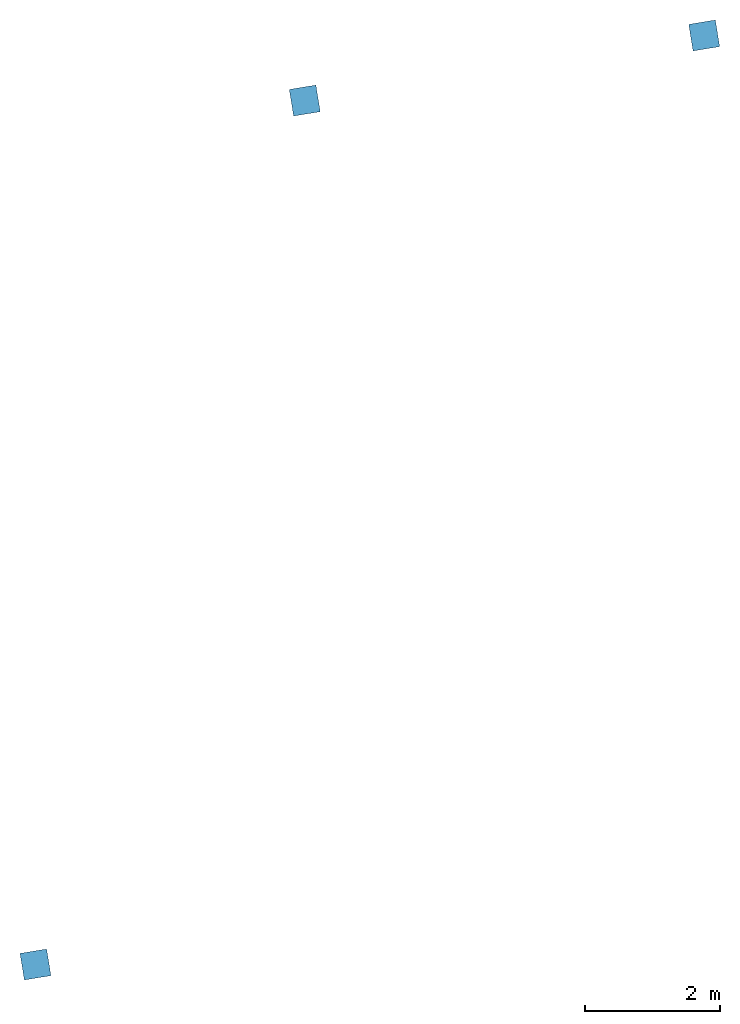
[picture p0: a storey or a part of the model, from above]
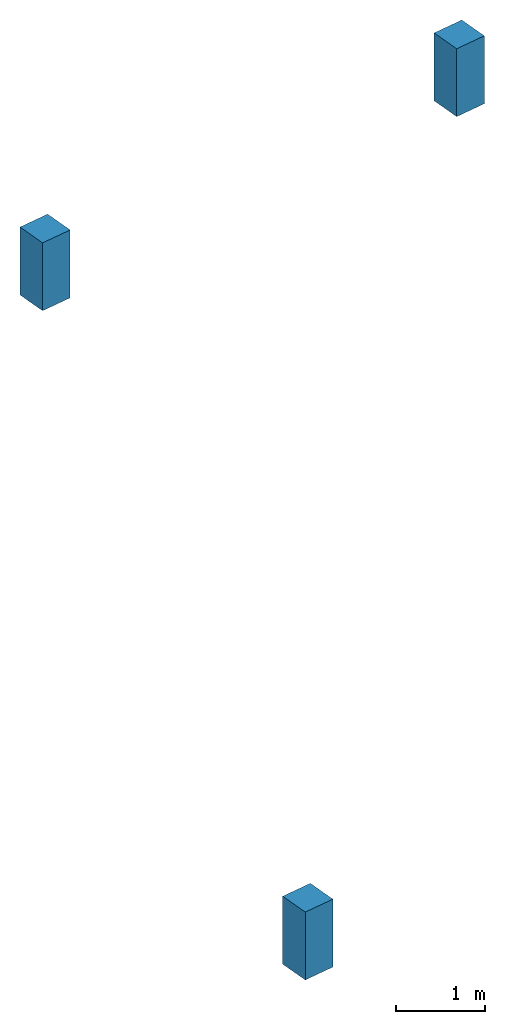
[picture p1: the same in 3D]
Properties of the parts of a building model (IFC2X3), part 1 of 2

# File
Description: ViewDefinition [CoordinationView_V2.0]
File name: BR001-350-201.1.IFC (Edited by Naviate Simple BIM 2022 version 6)
Time: 2026-03-27T10:15:47+01:00
Written by: ODA SDAI 24.12
Made in: Autodesk Revit 25.4.41.14 (ENU) - IFC 25.4.0.27

# IfcProject, 01. Avinor Drift
LongName: Terminal 2 . Satellitt; Phase: Som Bygget

# IfcSite (5)
RefElevation: 0 mm
Name | RefLatitude | RefLongitude
4 x Default | 60, 17, 20, 899658 | 5, 13, 37, 654037
Default | 42, 24, 53, 508911 | -71, -15, -29, -58837

# IfcBuilding (5)
Name | LongName
br001-a-200-1-0001 | br001-a-200-1-0001

3 x Bygning (endres i Project Information) | Bygning (endres i Project Information)

# IfcBuildingStorey: Level:Level - BR001_ARK (4)
In: br001-a-200-1-0001
Name | LongName | Elevation (mm)
H01-Nivå D+0,36 | H01-Nivå D+0,36 | 51360
H02-Nivå F-3,5 m | H02-Nivå F-3,5 m | 55500
H03-Nivå G-5m | H03-Nivå G-5m | 59000
H03-Nivå G-4,3m | H03-Nivå G-4,3m | 59700

# IfcBuildingStorey: Level:Level Elektro, H01-Nivå D+0,36
In: Bygning (endres i Project Information)
LongName: H01-Nivå D+0,36; Elevation: 51360 mm

# IfcBuildingStorey: Level:NO_Nivå_Meter-VVS (3)
In: Bygning (endres i Project Information)
Name | LongName | Elevation (mm)
2 x H01-Nivå D+0,36 | H01-Nivå D+0,36 | 51360
H02-Nivå F-3,5 m | H02-Nivå F-3,5 m | 55500

# IfcBuildingStorey: Level:NSW Kote - Triangel med navn og kote, Arial 2 mm KP (4)
Name | LongName | Elevation (mm)
U01-Nivå B+3,1m | U01-Nivå B+3,1m | 47800
H01-Nivå D+0,36 | H01-Nivå D+0,36 | 51360
H02-Nivå F-3,5 m | H02-Nivå F-3,5 m | 55500
H03-Nivå G-5m | H03-Nivå G-5m | 59000

# IfcBeam: 650*400 (14)
Description: 650*400
ePset_Simplebim - Assembly Level: Leaf
Pset_BeamCommon - Reference: 650*400
Name | In | Material | Width (Simplebim) (mm) | Volume, net (Simplebim) (m3) | Weight, as steel (Simplebim) (kg) | Area, sides, net (Simplebim) (m2) | Length (Simplebim) (mm) | Height (Simplebim) (mm) | Splitting
2 x PLASSTØPTBJELKE | H02-Nivå F-3,5 m | CONCRETE/C55/67 171016 | 400.026 | 1.56 | 12246 | 13.12 | 6000 | 650 | ORIGINAL
2 x PLASSTØPTBJELKE | H01-Nivå D+0,36 | CONCRETE/C55/67 171016 | 400.024 | 1.456 | 11429.6 | 12.28 | 5600 | 650 | ORIGINAL
2 x PLASSTØPTBJELKE | H01-Nivå D+0,36 | CONCRETE/C55/67 171016 | 5999.98 | 2.10217 | 16502.1 | 17.4991 | 6000.02 | 650 | ORIGINAL
2 x PLASSTØPTBJELKE | H02-Nivå F-3,5 m | CONCRETE/C55/67 171016 | 6282.82 | 2.20617 | 17318.5 | 18.3391 | 6282.86 | 650 | ORIGINAL
PLASSTØPTBJELKE | H02-Nivå F-3,5 m |  | 3469 | 1.17133 | 9194.92 | 9.98072 | 3469 | 650 | RESULT
PLASSTØPTBJELKE | H02-Nivå F-3,5 m |  | 1004 | 0.265197 | 2081.8 | 2.66197 | 1004 | 650 | RESULT
PLASSTØPTBJELKE | H02-Nivå F-3,5 m |  | 400 | 0.375058 | 2944.2 | 3.65701 | 1642 | 650 | RESULT
PLASSTØPTBJELKE | H01-Nivå D+0,36 |  | 3469 | 0.702796 | 5516.95 | 7.43006 | 3469 | 390 | RESULT
PLASSTØPTBJELKE | H01-Nivå D+0,36 |  | 862 | 0.127918 | 1004.16 | 1.60758 | 862 | 390 | RESULT
PLASSTØPTBJELKE | H01-Nivå D+0,36 |  | 400 | 0.323058 | 2536 | 3.23701 | 1442 | 650 | RESULT

# IfcBeam: DT450*2400-100-50-1200-0-200-0.3 (31)
Description: DT450*2400-100-50-1200-0-200-0.3
ePset_LocationTool - Splitting: RESULT
Pset_BeamCommon - Reference: DT450*2400-100-50-1200-0-200-0.3
ePset_Simplebim - Assembly Level: Leaf
Name | In | Area, sides, net (Simplebim) (m2) | Weight, as steel (Simplebim) (kg) | Height (Simplebim) (mm) | Width (Simplebim) (mm) | Length (Simplebim) (mm) | Volume, net (Simplebim) (m3)
DT | H03-Nivå G-5m | 16.6656 | 4901.39 | 310 | 1300 | 10552 | 0.624381
DT | H03-Nivå G-5m | 14.4214 | 4235.4 | 310 | 1300 | 9352 | 0.539542
DT | H03-Nivå G-5m | 10.4855 | 3067.33 | 310 | 1300 | 6952 | 0.390743
DT | H03-Nivå G-5m | 6.5495 | 1899.26 | 310 | 1300 | 4552 | 0.241944
DT | H03-Nivå G-5m | 13.0057 | 3815.26 | 310 | 1300 | 8489 | 0.48602
DT | H03-Nivå G-5m | 7.23211 | 2094.3 | 310 | 1300 | 5603 | 0.26679
DT | H03-Nivå G-5m | 6.99753 | 2024.68 | 310 | 1300 | 5459 | 0.257921
DT | H03-Nivå G-5m | 14.8695 | 4361.09 | 310 | 1300 | 10260 | 0.555553
DT | H03-Nivå G-5m | 22.0255 | 6488.58 | 310 | 1300 | 14152 | 0.826571
DT | H03-Nivå G-5m | 17.9171 | 5272.82 | 310 | 1300 | 11483 | 0.671696
DT | H03-Nivå G-5m | 13.9812 | 4104.75 | 310 | 1300 | 9083 | 0.522898
DT | H03-Nivå G-5m | 10.0452 | 2936.68 | 310 | 1300 | 6683 | 0.374099
DT | H03-Nivå G-5m | 6.10921 | 1768.61 | 310 | 1300 | 4284 | 0.2253
DT | H03-Nivå G-5m | 2.17325 | 600.536 | 310 | 1300 | 1884 | 0.0765015
DT | H01-Nivå D+0,36 | 63.5049 | 17634.7 | 450 | 2400 | 10671 | 2.24646
DT | H01-Nivå D+0,36 | 49.7879 | 13764.2 | 450 | 2400 | 9039 | 1.75341
DT | H01-Nivå D+0,36 | 27.6263 | 7550.74 | 450 | 2400 | 6478 | 0.961878
DT | H01-Nivå D+0,36 | 55.1436 | 15262.4 | 450 | 2400 | 9902 | 1.94425
DT | H01-Nivå D+0,36 | 40.2152 | 11082 | 450 | 2400 | 7502 | 1.41172
DT | H01-Nivå D+0,36 | 25.1068 | 6861.85 | 450 | 2400 | 5102 | 0.874121
DT | H01-Nivå D+0,36 | 2.67767 | 642.249 | 450 | 952 | 1903 | 0.0818151
DT | H01-Nivå D+0,36 | 57.0378 | 15755 | 450 | 2400 | 11360 | 2.007
DT | H01-Nivå D+0,36 | 84.3066 | 23408.6 | 450 | 2400 | 14702 | 2.98198
DT | H01-Nivå D+0,36 | 2.29866 | 532.447 | 450 | 880 | 1759 | 0.0678277
DT | H01-Nivå D+0,36 | 26.8208 | 7314.69 | 450 | 2400 | 6559 | 0.931807
DT | H01-Nivå D+0,36 | 68.647 | 19034.7 | 450 | 2400 | 11809 | 2.4248
DT | H01-Nivå D+0,36 | 53.6337 | 14830.1 | 450 | 2400 | 9633 | 1.88918
DT | H01-Nivå D+0,36 | 38.3454 | 10570.3 | 450 | 2400 | 7234 | 1.34653
DT | H01-Nivå D+0,36 | 23.4169 | 6389.82 | 450 | 2400 | 4834 | 0.81399
DT | H01-Nivå D+0,36 | 8.23028 | 2157.01 | 450 | 2209 | 2434 | 0.274778
DT | H01-Nivå D+0,36 | 1.72906 | 452.529 | 450 | 731 | 1237 | 0.057647

# IfcBuildingElementProxy: RA4303 Dome Kamera SNC-RZ25P i tak:RA4303, RA4303 Dome Kamera SNC-RZ25P i tak:RA4303:2981881
In: H01-Nivå D+0,36
Type - Material: Plastic - White
Classification: RA001 (Uniformat)
ePset_LocationTool - Splitting: ORIGINAL
ePset_Simplebim - Assembly Level: Leaf
Pset_BuildingElementProxyCommon - Reference: RA4303 Dome Kamera SNC-RZ25P i tak:RA4303
ePset_SimplebimBasicQuantities - Length (Simplebim): 219.536 mm; Volume, net (Simplebim): 0.00247107 m3; Thickness (Simplebim): 140.004 mm; Height (Simplebim): 157.036 mm; Area, largest surface, net (Simplebim): 0.0438648 m2

# IfcColumn: 400*400 (9)
Description: 400*400
ePset_Simplebim - Assembly Level: Leaf
Pset_ColumnCommon - Reference: 400*400
Name | In | Weight, as steel (Simplebim) (kg) | Depth (Simplebim) (mm) | Width (Simplebim) (mm) | Height (Simplebim) (mm) | Volume, net (Simplebim) (m3) | Area, sides, net (Simplebim) (m2) | Splitting
PLASSTØPTSØYLE | H01-Nivå D+0,36 | 4458.8 | 400.002 | 400.002 | 3550 | 0.568 | 5.68 | ORIGINAL
PLASSTØPTSØYLE | H02-Nivå F-3,5 m | 5275.2 | 400.002 | 400.002 | 4200 | 0.672 | 6.71998 | ORIGINAL
PLASSTØPTSØYLE | H02-Nivå F-3,5 m | 5275.2 | 400.002 | 400.002 | 4200 | 0.672 | 6.72001 | ORIGINAL
PLASSTØPTSØYLE | H03-Nivå G-5m | 389.36 | 400 | 310 | 400 | 0.0496 | 0.496005 | RESULT
PLASSTØPTSØYLE | H03-Nivå G-5m | 389.36 | 400 | 310 | 400 | 0.0496 | 0.496012 | RESULT
PLASSTØPTSØYLE | H03-Nivå G-5m | 389.36 | 400 | 310 | 400 | 0.0496 | 0.495976 | RESULT
PLASSTØPTSØYLE | U01-Nivå B+3,1m | 1168.08 | 400 | 400 | 930 | 0.1488 | 1.48801 | RESULT
PLASSTØPTSØYLE | U01-Nivå B+3,1m | 1168.08 | 400 | 400 | 930 | 0.1488 | 1.488 | RESULT
PLASSTØPTSØYLE | U01-Nivå B+3,1m | 1168.08 | 400 | 400 | 930 | 0.1488 | 1.48798 | RESULT

# IfcColumn: Columns T5:Columns T2, Columns T5:Columns T2:11666136
In: H02-Nivå F-3,5 m
Type - PredefinedType: COLUMN; Material: <Unnamed>
ePset_Simplebim - Assembly Level: Leaf
ePset_LocationTool - Splitting: RESULT
ePset_SimplebimBasicQuantities - Weight, as steel (Simplebim): 706.5 kg; Depth (Simplebim): 400 mm; Height (Simplebim): 3000 mm; Width (Simplebim): 274.317 mm; Volume, net (Simplebim): 0.09 m3; Area, sides, net (Simplebim): 4.21561 m2
Pset_ColumnCommon - Reference: Columns T5:Columns T2

# IfcColumn: D500 (3)
In: H02-Nivå F-3,5 m
Description: D500
ePset_SimplebimBasicQuantities - Weight, as steel (Simplebim): 4620.39 kg; Volume, net (Simplebim): 0.588585 m3; Height (Simplebim): 3010 mm; Width (Simplebim): 500 mm; Depth (Simplebim): 500 mm; Area, sides, net (Simplebim): 4.72325 m2
ePset_Simplebim - Assembly Level: Leaf
Pset_ColumnCommon - Reference: D500
ePset_LocationTool - Splitting: ORIGINAL

# IfcColumn: D600 (6)
Description: D600
ePset_LocationTool - Splitting: ORIGINAL
ePset_SimplebimBasicQuantities - Width (Simplebim): 600 mm; Depth (Simplebim): 600 mm; Height (Simplebim): 1190 mm; Weight, as steel (Simplebim): 2630.4 kg; Volume, net (Simplebim): 0.335083 m3
ePset_Simplebim - Assembly Level: Leaf
Pset_ColumnCommon - Reference: D600
Name | In | Area, sides, net (Simplebim) (m2)
PLASSTØPTSØYLE | H01-Nivå D+0,36 | 2.24078
PLASSTØPTSØYLE | H02-Nivå F-3,5 m | 2.24078
PLASSTØPTSØYLE | H01-Nivå D+0,36 | 2.24081
PLASSTØPTSØYLE | H02-Nivå F-3,5 m | 2.24081
PLASSTØPTSØYLE | H01-Nivå D+0,36 | 2.2408
PLASSTØPTSØYLE | H02-Nivå F-3,5 m | 2.2408

# IfcColumn: NSW Søyle - Betong rektangulær:400 x 400 mm (10)
Type - PredefinedType: COLUMN; Material: _NSW Betong
ePset_Simplebim - Assembly Level: Leaf
ePset_SimplebimBasicQuantities - Depth (Simplebim): 400 mm
Pset_ColumnCommon - Reference: NSW Søyle - Betong rektangulær:400 x 400 mm
Name (NSW Søyle - Betong rektangulær:400 x 400 mm:...) | In | Splitting | Volume, net (Simplebim) (m3) | Area, sides, net (Simplebim) (m2) | Width (Simplebim) (mm) | Height (Simplebim) (mm) | Weight, as steel (Simplebim) (kg)
865039 | H02-Nivå F-3,5 m | ORIGINAL | 0.01598 | 0.157657 | 100 | 400 | 125.443
865040 | H02-Nivå F-3,5 m | ORIGINAL | 0.01598 | 0.157657 | 100 | 400 | 125.443
865089 | H02-Nivå F-3,5 m | ORIGINAL | 0.01598 | 0.157657 | 100 | 400 | 125.443
746158 | H03-Nivå G-5m | RESULT | 0.06392 | 0.630662 | 400 | 400 | 501.772
746160 | H03-Nivå G-5m | RESULT | 0.06392 | 0.630564 | 400 | 400 | 501.772
6231712 | H03-Nivå G-5m | RESULT | 0.06392 | 0.630555 | 400 | 400 | 501.772
746157 | H03-Nivå G-5m | RESULT | 0.06392 | 0.630566 | 400 | 400 | 501.772
263699 | H01-Nivå D+0,36 | RESULT | 0.1598 | 1.57657 | 400 | 1000 | 1254.43
263748 | H01-Nivå D+0,36 | RESULT | 0.1598 | 1.57657 | 400 | 1000 | 1254.43
263698 | H01-Nivå D+0,36 | RESULT | 0.1598 | 1.57657 | 400 | 1000 | 1254.43

# IfcColumn: NSW Søyle - Betong rund:ø500 mm (6)
Type - PredefinedType: COLUMN; Material: _NSW Betong
ePset_Simplebim - Assembly Level: Leaf
ePset_SimplebimBasicQuantities - Width (Simplebim): 500 mm; Depth (Simplebim): 500 mm
Pset_ColumnCommon - Reference: NSW Søyle - Betong rund:ø500 mm
Name (NSW Søyle - Betong rund:ø500 mm:...) | In | Area, sides, net (Simplebim) (m2) | Weight, as steel (Simplebim) (kg) | Height (Simplebim) (mm) | Volume, net (Simplebim) (m3) | Splitting
2013234 | H02-Nivå F-3,5 m | 5.56924 | 5444.03 | 3550 | 0.693507 | ORIGINAL
2013349 | H02-Nivå F-3,5 m | 5.56924 | 5444.03 | 3550 | 0.693507 | ORIGINAL
2013424 | H02-Nivå F-3,5 m | 5.56924 | 5444.03 | 3550 | 0.693507 | ORIGINAL
263727 | H01-Nivå D+0,36 | 1.5688 | 1533.53 | 1000 | 0.195354 | RESULT
263725 | H01-Nivå D+0,36 | 1.5688 | 1533.53 | 1000 | 0.195354 | RESULT
263726 | H01-Nivå D+0,36 | 1.5688 | 1533.53 | 1000 | 0.195354 | RESULT

# IfcCovering: Pipe Insulation:GLAVA Rørskål ClimPipe Alu2, isol.kl.4, 45°C (14)
In: H01-Nivå D+0,36
Type - PredefinedType: INSULATION
Pset_CoveringCommon - Reference: Pipe Insulation:GLAVA Rørskål ClimPipe Alu2, isol.kl.4, 45°C
ePset_Simplebim - Assembly Level: Leaf
Name (Pipe Insulation:GLAVA Rørskål ClimPipe Alu2, isol.kl.4, 45°C:...) | Splitting | Volume, net (Simplebim) (m3) | Length (Simplebim) (mm) | Height (Simplebim) (mm) | Width (Simplebim) (mm) | Area, largest surface, net (Simplebim) (m2)
5639866 | ORIGINAL | 0.000216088 | 92 | 55 | 55 | 0.0158511 | Material: 3200.002 Retur
5639867 | ORIGINAL | 0.000147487 | 57.7 | 57.4 | 57.7 | 0.00888691 | Material: 3200.002 Retur
5639879 | ORIGINAL | 0.000147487 | 57.7 | 57.4 | 57.7 | 0.00888691 | Material: 3200.002 Retur
5652195 | ORIGINAL | 0.00398234 | 137 | 133.5 | 133.5 | 0.0545841 | Material: 3200.002 Retur
5652198 | ORIGINAL | 0.00398234 | 137 | 133.5 | 133.5 | 0.0545841 | Material: 3200.003 Tur
5639766 | RESULT | 0.010846 | 4634 | 55 | 55 | 0.00333145
5639854 | RESULT | 0.0108508 | 4635 | 55 | 55 | 0.00332707
5639878 | RESULT | 0.0112003 | 4785 | 55 | 55 | 0.0033372
5636214 | RESULT | 0.0183281 | 1447 | 134 | 134 | 0.0197809
5637673 | RESULT | 0.0132978 | 1087 | 134 | 134 | 0.0197788
5643278 | RESULT | 0.017064 | 1289 | 134 | 134 | 0.0197096
5643302 | RESULT | 0.0240394 | 1789 | 134 | 134 | 0.0197386
5643582 | RESULT | 0.0170723 | 1289 | 134 | 134 | 0.0197264
5643626 | RESULT | 0.0240681 | 1789 | 134 | 134 | 0.0197632

# IfcCovering: Pipe Insulation:GLAVA avløpsisol. slange økende 19mm (15,5-25,0) (8)
In: H01-Nivå D+0,36
Type - PredefinedType: INSULATION
ePset_Simplebim - Assembly Level: Leaf
Pset_CoveringCommon - Reference: Pipe Insulation:GLAVA avløpsisol. slange økende 19mm (15,5-25,0)
Name (Pipe Insulation:GLAVA avløpsisol. slange økende 19mm (15,5-25,0):...) | Area, largest surface, net (Simplebim) (m2) | Length (Simplebim) (mm) | Width (Simplebim) (mm) | Height (Simplebim) (mm) | Volume, net (Simplebim) (m3) | Splitting
5652205 | 0.057121 | 156.55 | 156.55 | 120.1 | 0.00169602 | ORIGINAL | Material: 3700.001 Tur
5652221 | 0.057121 | 156.55 | 156.55 | 120.1 | 0.00169602 | ORIGINAL | Material: 3700.001 Retur
5633254 | 0.0158927 | 2382 | 120 | 120 | 0.0253943 | RESULT
5633602 | 0.0159149 | 2782 | 120 | 120 | 0.0299214 | RESULT
5643661 | 0.0158805 | 2450 | 120 | 120 | 0.0267935 | RESULT
5643674 | 0.0158134 | 2450 | 120 | 120 | 0.0268114 | RESULT
5643702 | 0.0158744 | 2970 | 120 | 120 | 0.0326307 | RESULT
5643715 | 0.015876 | 2970 | 120 | 120 | 0.0326906 | RESULT

# IfcCurtainWall: Curtain Wall:A243 Innvendig glassvegg, Curtain Wall:A243 Innvendig glassvegg:12530820
In: H02-Nivå F-3,5 m
ePset_Simplebim - Assembly Level: Topmost
Pset_CurtainWallCommon - Reference: Curtain Wall:A243 Innvendig glassvegg
ePset_SimplebimBasicQuantities - Volume, net (Simplebim): 0.17462 m3; Length: 2338.5 mm; Width: 150 mm; Height: 2960 mm

# IfcDistributionControlElement: Brannslange:Brannslange, Brannslange:Brannslange:12630190
In: H02-Nivå F-3,5 m
Type - Material: Black, Aluminum, Anodized Red
ePset_LocationTool - Splitting: ORIGINAL
ePset_Simplebim - Assembly Level: Leaf

# IfcDistributionControlElement: Manuell melder:Manuell melder, Manuell melder:Manuell melder:12630332
In: H02-Nivå F-3,5 m
Type - Material: <Unnamed>, Aluminum, Anodized Red, Glass
ePset_Simplebim - Assembly Level: Leaf
ePset_LocationTool - Splitting: ORIGINAL

# IfcDistributionControlElement: Rømningsretning (4):Rømningsretning (4), Rømningsretning (4):Rømningsretning (4):12609138
In: H02-Nivå F-3,5 m
Type - Material: Green
ePset_LocationTool - Splitting: ORIGINAL
ePset_Simplebim - Assembly Level: Leaf

# IfcDistributionPort (538)
Description: Flow
ePset_Simplebim - Assembly Level: Leaf
Name | FlowDirection | Group
Port_2981881_1 | SOURCEANDSINK
Port_2981881_2 | SOURCEANDSINK
Port_2981881_3 | SOURCEANDSINK
Port_2981881_4 | SOURCEANDSINK
Port_2985146_1 | SOURCEANDSINK
Port_5561182_1 | SOURCEANDSINK | 36.03 Tilluft 1.etg nord og øst + nordfløy: 1
Port_5561251_1 | SOURCEANDSINK | 36.03 Tilluft 1.etg nord og øst + nordfløy: 1
Port_5561555_1 | SOURCEANDSINK | 36.03 Tilluft 1.etg nord og øst + nordfløy: 1
Port_5469861_0 | SOURCEANDSINK | 36.03 Tilluft 1.etg nord og øst + nordfløy: 1
Port_5469861_1 | SOURCEANDSINK | 36.03 Tilluft 1.etg nord og øst + nordfløy: 1
Port_5469910_2 | SOURCEANDSINK | 36.03 Tilluft 1.etg nord og øst + nordfløy: 1
Port_5469879_0 | SOURCEANDSINK | 36.03 Tilluft 1.etg nord og øst + nordfløy: 1
Port_5469910_3 | SOURCEANDSINK | 36.03 Tilluft 1.etg nord og øst + nordfløy: 1
Port_5469879_1 | SOURCEANDSINK | 36.03 Tilluft 1.etg nord og øst + nordfløy: 1
InPort_5469979_0 | SINK | 36.03 Tilluft 1.etg nord og øst + nordfløy: 1
OutPort_5469910_1 | SOURCE | 36.03 Tilluft 1.etg nord og øst + nordfløy: 1
InPort_5470001_1 | SINK | 36.03 Tilluft 1.etg nord og øst + nordfløy: 1
OutPort_5469979_1 | SOURCE | 36.03 Tilluft 1.etg nord og øst + nordfløy: 1
Port_5470043_0 | SOURCEANDSINK | 36.03 Tilluft 1.etg nord og øst + nordfløy: 1
Port_5561551_1 | SOURCEANDSINK | 36.03 Tilluft 1.etg nord og øst + nordfløy: 1
Port_5470043_1 | SOURCEANDSINK | 36.03 Tilluft 1.etg nord og øst + nordfløy: 1
Port_5470047_2 | SOURCEANDSINK | 36.03 Tilluft 1.etg nord og øst + nordfløy: 1
Port_5470045_0 | SOURCEANDSINK | 36.03 Tilluft 1.etg nord og øst + nordfløy: 1
Port_5470047_3 | SOURCEANDSINK | 36.03 Tilluft 1.etg nord og øst + nordfløy: 1
Port_5470045_1 | SOURCEANDSINK | 36.03 Tilluft 1.etg nord og øst + nordfløy: 1
InPort_5470051_0 | SINK | 36.03 Tilluft 1.etg nord og øst + nordfløy: 1
OutPort_5470047_1 | SOURCE | 36.03 Tilluft 1.etg nord og øst + nordfløy: 1
InPort_5470053_1 | SINK | 36.03 Tilluft 1.etg nord og øst + nordfløy: 1
OutPort_5470051_1 | SOURCE | 36.03 Tilluft 1.etg nord og øst + nordfløy: 1
Port_5470421_0 | SOURCEANDSINK | 36.03 Tilluft 1.etg nord og øst + nordfløy: 1
Port_5470427_2 | SOURCEANDSINK | 36.03 Tilluft 1.etg nord og øst + nordfløy: 1
Port_5470421_1 | SOURCEANDSINK | 36.03 Tilluft 1.etg nord og øst + nordfløy: 1
Port_5561259_2 | SOURCEANDSINK | 36.03 Tilluft 1.etg nord og øst + nordfløy: 1
Port_5470425_0 | SOURCEANDSINK | 36.03 Tilluft 1.etg nord og øst + nordfløy: 1
Port_5470427_3 | SOURCEANDSINK | 36.03 Tilluft 1.etg nord og øst + nordfløy: 1
Port_5470425_1 | SOURCEANDSINK | 36.03 Tilluft 1.etg nord og øst + nordfløy: 1
Port_5470427_1 | SOURCEANDSINK | 36.03 Tilluft 1.etg nord og øst + nordfløy: 1
InPort_5472319_0 | SINK | 36.03 Tilluft 1.etg nord og øst + nordfløy: 1
OutPort_5472323_2 | SOURCE | 36.03 Tilluft 1.etg nord og øst + nordfløy: 1
InPort_5472456_1 | SINK | 36.03 Tilluft 1.etg nord og øst + nordfløy: 1
OutPort_5472319_1 | SOURCE | 36.03 Tilluft 1.etg nord og øst + nordfløy: 1
Port_5472321_0 | SOURCEANDSINK | 36.03 Tilluft 1.etg nord og øst + nordfløy: 1
Port_5472323_3 | SOURCEANDSINK | 36.03 Tilluft 1.etg nord og øst + nordfløy: 1
Port_5472321_1 | SOURCEANDSINK | 36.03 Tilluft 1.etg nord og øst + nordfløy: 1
Port_5472323_1 | SOURCEANDSINK | 36.03 Tilluft 1.etg nord og øst + nordfløy: 1
Port_5472345_1 | SOURCEANDSINK | 36.03 Tilluft 1.etg nord og øst + nordfløy: 1
Port_5472329_0 | SOURCEANDSINK | 36.03 Tilluft 1.etg nord og øst + nordfløy: 1
Port_5472331_3 | SOURCEANDSINK | 36.03 Tilluft 1.etg nord og øst + nordfløy: 1
Port_5472329_1 | SOURCEANDSINK | 36.03 Tilluft 1.etg nord og øst + nordfløy: 1
Port_5472331_1 | SOURCEANDSINK | 36.03 Tilluft 1.etg nord og øst + nordfløy: 1
Port_5472347_1 | SOURCEANDSINK | 36.03 Tilluft 1.etg nord og øst + nordfløy: 1
Port_5472331_2 | SOURCEANDSINK | 36.03 Tilluft 1.etg nord og øst + nordfløy: 1
Port_5472345_0 | SOURCEANDSINK | 36.03 Tilluft 1.etg nord og øst + nordfløy: 1
Port_5472337_0 | SOURCEANDSINK | 36.03 Tilluft 1.etg nord og øst + nordfløy: 1
Port_5472339_3 | SOURCEANDSINK | 36.03 Tilluft 1.etg nord og øst + nordfløy: 1
Port_5472337_1 | SOURCEANDSINK | 36.03 Tilluft 1.etg nord og øst + nordfløy: 1
Port_5472339_1 | SOURCEANDSINK | 36.03 Tilluft 1.etg nord og øst + nordfløy: 1
Port_5472493_0 | SOURCEANDSINK | 36.03 Tilluft 1.etg nord og øst + nordfløy: 1
Port_5472339_2 | SOURCEANDSINK | 36.03 Tilluft 1.etg nord og øst + nordfløy: 1
Port_5472347_0 | SOURCEANDSINK | 36.03 Tilluft 1.etg nord og øst + nordfløy: 1
Port_5472493_1 | SOURCEANDSINK | 36.03 Tilluft 1.etg nord og øst + nordfløy: 1
Port_5561178_1 | SOURCEANDSINK | 36.03 Tilluft 1.etg nord og øst + nordfløy: 1
InPort_5472589_0 | SINK | 36.03 Tilluft 1.etg nord og øst + nordfløy: 1
OutPort_5472593_2 | SOURCE | 36.03 Tilluft 1.etg nord og øst + nordfløy: 1
InPort_5472611_1 | SINK | 36.03 Tilluft 1.etg nord og øst + nordfløy: 1
OutPort_5472589_1 | SOURCE | 36.03 Tilluft 1.etg nord og øst + nordfløy: 1
Port_5472591_0 | SOURCEANDSINK | 36.03 Tilluft 1.etg nord og øst + nordfløy: 1
Port_5472593_3 | SOURCEANDSINK | 36.03 Tilluft 1.etg nord og øst + nordfløy: 1
Port_5472591_1 | SOURCEANDSINK | 36.03 Tilluft 1.etg nord og øst + nordfløy: 1
Port_5472597_1 | SOURCEANDSINK | 36.03 Tilluft 1.etg nord og øst + nordfløy: 1
Port_5472593_1 | SOURCEANDSINK | 36.03 Tilluft 1.etg nord og øst + nordfløy: 1
Port_5472607_1 | SOURCEANDSINK | 36.03 Tilluft 1.etg nord og øst + nordfløy: 1
Port_5472595_0 | SOURCEANDSINK | 36.03 Tilluft 1.etg nord og øst + nordfløy: 1
Port_5472597_2 | SOURCEANDSINK | 36.03 Tilluft 1.etg nord og øst + nordfløy: 1
Port_5472595_1 | SOURCEANDSINK | 36.03 Tilluft 1.etg nord og øst + nordfløy: 1
Port_5472599_0 | SOURCEANDSINK | 36.03 Tilluft 1.etg nord og øst + nordfløy: 1
Port_5472601_3 | SOURCEANDSINK | 36.03 Tilluft 1.etg nord og øst + nordfløy: 1
Port_5472599_1 | SOURCEANDSINK | 36.03 Tilluft 1.etg nord og øst + nordfløy: 1
Port_5472605_1 | SOURCEANDSINK | 36.03 Tilluft 1.etg nord og øst + nordfløy: 1
Port_5472601_1 | SOURCEANDSINK | 36.03 Tilluft 1.etg nord og øst + nordfløy: 1
Port_5472601_2 | SOURCEANDSINK | 36.03 Tilluft 1.etg nord og øst + nordfløy: 1
Port_5472607_0 | SOURCEANDSINK | 36.03 Tilluft 1.etg nord og øst + nordfløy: 1
Port_5472603_0 | SOURCEANDSINK | 36.03 Tilluft 1.etg nord og øst + nordfløy: 1
Port_5472605_2 | SOURCEANDSINK | 36.03 Tilluft 1.etg nord og øst + nordfløy: 1
Port_5472603_1 | SOURCEANDSINK | 36.03 Tilluft 1.etg nord og øst + nordfløy: 1
InPort_5473220_0 | SINK | 36.03 Tilluft 1.etg nord og øst + nordfløy: 1
InPort_5473337_1 | SINK | 36.03 Tilluft 1.etg nord og øst + nordfløy: 1
OutPort_5473220_1 | SOURCE | 36.03 Tilluft 1.etg nord og øst + nordfløy: 1
OutPort_5480765_1 | SOURCE | 36.03 Avtrekk 1.etg nord og øst + nordfløy: 1
Port_5480794_0 | SOURCEANDSINK | 36.03 Avtrekk 1.etg nord og øst + nordfløy: 1
Port_5480925_2 | SOURCEANDSINK | 36.03 Avtrekk 1.etg nord og øst + nordfløy: 1
Port_5480794_1 | SOURCEANDSINK | 36.03 Avtrekk 1.etg nord og øst + nordfløy: 1
Port_5480989_1 | SOURCEANDSINK | 36.03 Avtrekk 1.etg nord og øst + nordfløy: 1
Port_5480925_3 | SOURCEANDSINK | 36.03 Avtrekk 1.etg nord og øst + nordfløy: 1
Port_5480925_1 | SOURCEANDSINK | 36.03 Avtrekk 1.etg nord og øst + nordfløy: 1
Port_5481045_1 | SOURCEANDSINK | 36.03 Avtrekk 1.etg nord og øst + nordfløy: 1
Port_5480973_3 | SOURCEANDSINK | 36.03 Avtrekk 1.etg nord og øst + nordfløy: 1
InPort_5480973_1 | SINK | 36.03 Avtrekk 1.etg nord og øst + nordfløy: 1
OutPort_5481057_0 | SOURCE | 36.03 Avtrekk 1.etg nord og øst + nordfløy: 1
Port_5480973_2 | SOURCEANDSINK | 36.03 Avtrekk 1.etg nord og øst + nordfløy: 1
Port_5481045_0 | SOURCEANDSINK | 36.03 Avtrekk 1.etg nord og øst + nordfløy: 1
Port_5480989_3 | SOURCEANDSINK | 36.03 Avtrekk 1.etg nord og øst + nordfløy: 1
Port_5480989_2 | SOURCEANDSINK | 36.03 Avtrekk 1.etg nord og øst + nordfløy: 1
Port_5481109_0 | SOURCEANDSINK | 36.03 Avtrekk 1.etg nord og øst + nordfløy: 1
InPort_5481057_1 | SINK | 36.03 Avtrekk 1.etg nord og øst + nordfløy: 1
OutPort_5481084_1 | SOURCE | 36.03 Avtrekk 1.etg nord og øst + nordfløy: 1
Port_5481109_1 | SOURCEANDSINK | 36.03 Avtrekk 1.etg nord og øst + nordfløy: 1
Port_5561382_1 | SOURCEANDSINK | 36.03 Avtrekk 1.etg nord og øst + nordfløy: 1
Port_5481543_1 | SOURCEANDSINK | 36.03 Avtrekk 1.etg nord og øst + nordfløy: 1
Port_5481543_3 | SOURCEANDSINK | 36.03 Avtrekk 1.etg nord og øst + nordfløy: 1
Port_5481543_2 | SOURCEANDSINK | 36.03 Avtrekk 1.etg nord og øst + nordfløy: 1
Port_5481745_0 | SOURCEANDSINK | 36.03 Avtrekk 1.etg nord og øst + nordfløy: 1
Port_5481745_1 | SOURCEANDSINK | 36.03 Avtrekk 1.etg nord og øst + nordfløy: 1
Port_5561336_1 | SOURCEANDSINK | 36.03 Avtrekk 1.etg nord og øst + nordfløy: 1
Port_5481859_0 | SOURCEANDSINK | 36.03 Avtrekk 1.etg nord og øst + nordfløy: 1
Port_5481863_2 | SOURCEANDSINK | 36.03 Avtrekk 1.etg nord og øst + nordfløy: 1
Port_5481859_1 | SOURCEANDSINK | 36.03 Avtrekk 1.etg nord og øst + nordfløy: 1
Port_5482037_1 | SOURCEANDSINK | 36.03 Avtrekk 1.etg nord og øst + nordfløy: 1
Port_5481863_3 | SOURCEANDSINK | 36.03 Avtrekk 1.etg nord og øst + nordfløy: 1
Port_5481863_1 | SOURCEANDSINK | 36.03 Avtrekk 1.etg nord og øst + nordfløy: 1
Port_5481865_0 | SOURCEANDSINK | 36.03 Avtrekk 1.etg nord og øst + nordfløy: 1
Port_5481865_1 | SOURCEANDSINK | 36.03 Avtrekk 1.etg nord og øst + nordfløy: 1
Port_5482037_3 | SOURCEANDSINK | 36.03 Avtrekk 1.etg nord og øst + nordfløy: 1
Port_5482037_2 | SOURCEANDSINK | 36.03 Avtrekk 1.etg nord og øst + nordfløy: 1
Port_5482143_1 | SOURCEANDSINK | 36.03 Avtrekk 1.etg nord og øst + nordfløy: 1
Port_5482051_3 | SOURCEANDSINK | 36.03 Avtrekk 1.etg nord og øst + nordfløy: 1
Port_5482051_1 | SOURCEANDSINK | 36.03 Avtrekk 1.etg nord og øst + nordfløy: 1
Port_5482143_0 | SOURCEANDSINK | 36.03 Avtrekk 1.etg nord og øst + nordfløy: 1
Port_5482051_2 | SOURCEANDSINK | 36.03 Avtrekk 1.etg nord og øst + nordfløy: 1
Port_5482153_1 | SOURCEANDSINK | 36.03 Avtrekk 1.etg nord og øst + nordfløy: 1
Port_5482065_3 | SOURCEANDSINK | 36.03 Avtrekk 1.etg nord og øst + nordfløy: 1
Port_5482065_1 | SOURCEANDSINK | 36.03 Avtrekk 1.etg nord og øst + nordfløy: 1
Port_5482153_0 | SOURCEANDSINK | 36.03 Avtrekk 1.etg nord og øst + nordfløy: 1
Port_5482065_2 | SOURCEANDSINK | 36.03 Avtrekk 1.etg nord og øst + nordfløy: 1
Port_5482163_1 | SOURCEANDSINK | 36.03 Avtrekk 1.etg nord og øst + nordfløy: 1
Port_5482079_3 | SOURCEANDSINK | 36.03 Avtrekk 1.etg nord og øst + nordfløy: 1
Port_5482079_1 | SOURCEANDSINK | 36.03 Avtrekk 1.etg nord og øst + nordfløy: 1
Port_5482163_0 | SOURCEANDSINK | 36.03 Avtrekk 1.etg nord og øst + nordfløy: 1
InPort_5482079_2 | SINK | 36.03 Avtrekk 1.etg nord og øst + nordfløy: 1
OutPort_5482188_0 | SOURCE | 36.03 Avtrekk 1.etg nord og øst + nordfløy: 1
InPort_5482188_1 | SINK | 36.03 Avtrekk 1.etg nord og øst + nordfløy: 1
OutPort_5482213_1 | SOURCE | 36.03 Avtrekk 1.etg nord og øst + nordfløy: 1
Port_5483259_2 | SOURCEANDSINK | 36.03 Avtrekk 1.etg nord og øst + nordfløy: 1
Port_5483225_0 | SOURCEANDSINK | 36.03 Avtrekk 1.etg nord og øst + nordfløy: 1
Port_5483259_3 | SOURCEANDSINK | 36.03 Avtrekk 1.etg nord og øst + nordfløy: 1
Port_5483225_1 | SOURCEANDSINK | 36.03 Avtrekk 1.etg nord og øst + nordfløy: 1
Port_5483374_1 | SOURCEANDSINK | 36.03 Avtrekk 1.etg nord og øst + nordfløy: 1
Port_5483259_1 | SOURCEANDSINK | 36.03 Avtrekk 1.etg nord og øst + nordfløy: 1
Port_5483528_1 | SOURCEANDSINK | 36.03 Avtrekk 1.etg nord og øst + nordfløy: 1
Port_5483274_0 | SOURCEANDSINK | 36.03 Avtrekk 1.etg nord og øst + nordfløy: 1
Port_5483528_2 | SOURCEANDSINK | 36.03 Avtrekk 1.etg nord og øst + nordfløy: 1
Port_5483274_1 | SOURCEANDSINK | 36.03 Avtrekk 1.etg nord og øst + nordfløy: 1
Port_5483554_2 | SOURCEANDSINK | 36.03 Avtrekk 1.etg nord og øst + nordfløy: 1
Port_5483364_0 | SOURCEANDSINK | 36.03 Avtrekk 1.etg nord og øst + nordfløy: 1
Port_5483374_2 | SOURCEANDSINK | 36.03 Avtrekk 1.etg nord og øst + nordfløy: 1
Port_5483364_1 | SOURCEANDSINK | 36.03 Avtrekk 1.etg nord og øst + nordfløy: 1
Port_5483484_0 | SOURCEANDSINK | 36.03 Avtrekk 1.etg nord og øst + nordfløy: 1
Port_5483520_1 | SOURCEANDSINK | 36.03 Avtrekk 1.etg nord og øst + nordfløy: 1
Port_5483484_1 | SOURCEANDSINK | 36.03 Avtrekk 1.etg nord og øst + nordfløy: 1
Port_5483518_0 | SOURCEANDSINK | 36.03 Avtrekk 1.etg nord og øst + nordfløy: 1
Port_5483520_2 | SOURCEANDSINK | 36.03 Avtrekk 1.etg nord og øst + nordfløy: 1
Port_5483518_1 | SOURCEANDSINK | 36.03 Avtrekk 1.etg nord og øst + nordfløy: 1
Port_5483554_3 | SOURCEANDSINK | 36.03 Avtrekk 1.etg nord og øst + nordfløy: 1
InPort_5483554_1 | SINK | 36.03 Avtrekk 1.etg nord og øst + nordfløy: 1
OutPort_5483574_0 | SOURCE | 36.03 Avtrekk 1.etg nord og øst + nordfløy: 1
InPort_5483574_1 | SINK | 36.03 Avtrekk 1.etg nord og øst + nordfløy: 1
OutPort_5483604_1 | SOURCE | 36.03 Avtrekk 1.etg nord og øst + nordfløy: 1
Port_5561340_1 | SOURCEANDSINK | 36.03 Avtrekk 1.etg nord og øst + nordfløy: 1
Port_5561386_1 | SOURCEANDSINK | 36.03 Avtrekk 1.etg nord og øst + nordfløy: 1
Port_5508675_2 | SOURCEANDSINK | 36.26 Tilluft Bagasjehall 1.etg: 1
Port_5508643_0 | SOURCEANDSINK | 36.26 Tilluft Bagasjehall 1.etg: 1
Port_5508675_3 | SOURCEANDSINK | 36.26 Tilluft Bagasjehall 1.etg: 1
Port_5508643_1 | SOURCEANDSINK | 36.26 Tilluft Bagasjehall 1.etg: 1
Port_5508675_1 | SOURCEANDSINK | 36.26 Tilluft Bagasjehall 1.etg: 1
Port_5514940_1 | SOURCEANDSINK | 36.26 Avtrekk Bagasjehall 1.etg: 1
Port_5514725_0 | SOURCEANDSINK | 36.26 Avtrekk Bagasjehall 1.etg: 1
Port_5514940_2 | SOURCEANDSINK | 36.26 Avtrekk Bagasjehall 1.etg: 1
Port_5514725_1 | SOURCEANDSINK | 36.26 Avtrekk Bagasjehall 1.etg: 1
Port_5561175_0 | SOURCEANDSINK | 36.03 Tilluft 1.etg nord og øst + nordfløy: 1
Port_5561182_2 | SOURCEANDSINK | 36.03 Tilluft 1.etg nord og øst + nordfløy: 1
Port_5561175_1 | SOURCEANDSINK | 36.03 Tilluft 1.etg nord og øst + nordfløy: 1
Port_5561178_2 | SOURCEANDSINK | 36.03 Tilluft 1.etg nord og øst + nordfløy: 1
Port_5561247_0 | SOURCEANDSINK | 36.03 Tilluft 1.etg nord og øst + nordfløy: 1
Port_5561251_2 | SOURCEANDSINK | 36.03 Tilluft 1.etg nord og øst + nordfløy: 1
Port_5561247_1 | SOURCEANDSINK | 36.03 Tilluft 1.etg nord og øst + nordfløy: 1
Port_5561259_1 | SOURCEANDSINK | 36.03 Tilluft 1.etg nord og øst + nordfløy: 1
Port_5561333_0 | SOURCEANDSINK | 36.03 Avtrekk 1.etg nord og øst + nordfløy: 1
Port_5561340_2 | SOURCEANDSINK | 36.03 Avtrekk 1.etg nord og øst + nordfløy: 1
Port_5561333_1 | SOURCEANDSINK | 36.03 Avtrekk 1.etg nord og øst + nordfløy: 1
Port_5561336_2 | SOURCEANDSINK | 36.03 Avtrekk 1.etg nord og øst + nordfløy: 1
Port_5561379_0 | SOURCEANDSINK | 36.03 Avtrekk 1.etg nord og øst + nordfløy: 1
Port_5561386_2 | SOURCEANDSINK | 36.03 Avtrekk 1.etg nord og øst + nordfløy: 1
Port_5561379_1 | SOURCEANDSINK | 36.03 Avtrekk 1.etg nord og øst + nordfløy: 1
Port_5561382_2 | SOURCEANDSINK | 36.03 Avtrekk 1.etg nord og øst + nordfløy: 1
Port_5561548_0 | SOURCEANDSINK | 36.03 Tilluft 1.etg nord og øst + nordfløy: 1
Port_5561555_2 | SOURCEANDSINK | 36.03 Tilluft 1.etg nord og øst + nordfløy: 1
Port_5561548_1 | SOURCEANDSINK | 36.03 Tilluft 1.etg nord og øst + nordfløy: 1
Port_5561551_2 | SOURCEANDSINK | 36.03 Tilluft 1.etg nord og øst + nordfløy: 1
Port_5534892_1 | SOURCEANDSINK | 3320.001.01 Brannslokking Sprinkler våt 2
Port_5534884_0 | SOURCEANDSINK | 3320.001.01 Brannslokking Sprinkler våt 2
Port_5534892_2 | SOURCEANDSINK | 3320.001.01 Brannslokking Sprinkler våt 2
Port_5534884_1 | SOURCEANDSINK | 3320.001.01 Brannslokking Sprinkler våt 2
Port_5534904_1 | SOURCEANDSINK | 3320.001.01 Brannslokking Sprinkler våt 2
Port_5534898_0 | SOURCEANDSINK | 3320.001.01 Brannslokking Sprinkler våt 2
Port_5534904_2 | SOURCEANDSINK | 3320.001.01 Brannslokking Sprinkler våt 2
Port_5534898_1 | SOURCEANDSINK | 3320.001.01 Brannslokking Sprinkler våt 2
Port_5534918_2 | SOURCEANDSINK | 3320.001.01 Brannslokking Sprinkler våt 2
Port_5534910_0 | SOURCEANDSINK | 3320.001.01 Brannslokking Sprinkler våt 2
Port_5534918_1 | SOURCEANDSINK | 3320.001.01 Brannslokking Sprinkler våt 2
Port_5534910_1 | SOURCEANDSINK | 3320.001.01 Brannslokking Sprinkler våt 2
Port_5534930_1 | SOURCEANDSINK | 3320.001.01 Brannslokking Sprinkler våt 2
Port_5534924_0 | SOURCEANDSINK | 3320.001.01 Brannslokking Sprinkler våt 2
Port_5534930_2 | SOURCEANDSINK | 3320.001.01 Brannslokking Sprinkler våt 2
Port_5534924_1 | SOURCEANDSINK | 3320.001.01 Brannslokking Sprinkler våt 2
Port_5538231_1 | SOURCEANDSINK | 3320.001.01 Brannslokking Sprinkler våt 2
Port_5535973_2 | SOURCEANDSINK | 3320.001.01 Brannslokking Sprinkler våt 248
Port_5535678_0 | SOURCEANDSINK | 3320.001.01 Brannslokking Sprinkler våt 248
Port_5535931_2 | SOURCEANDSINK | 3320.001.01 Brannslokking Sprinkler våt 248
Port_5535678_1 | SOURCEANDSINK | 3320.001.01 Brannslokking Sprinkler våt 248
Port_5535971_1 | SOURCEANDSINK | 3320.001.01 Brannslokking Sprinkler våt 248
Port_5535710_1 | SOURCEANDSINK | 3320.001.01 Brannslokking Sprinkler våt 248
Port_5535927_2 | SOURCEANDSINK | 3320.001.01 Brannslokking Sprinkler våt 248
Port_5535714_0 | SOURCEANDSINK | 3320.001.01 Brannslokking Sprinkler våt 248
Port_5535919_4 | SOURCEANDSINK | 3320.001.01 Brannslokking Sprinkler våt 248
Port_5535714_1 | SOURCEANDSINK | 3320.001.01 Brannslokking Sprinkler våt 248
Port_5535927_1 | SOURCEANDSINK | 3320.001.01 Brannslokking Sprinkler våt 248
Port_5535919_2 | SOURCEANDSINK | 3320.001.01 Brannslokking Sprinkler våt 248
Port_5535931_1 | SOURCEANDSINK | 3320.001.01 Brannslokking Sprinkler våt 248
Port_5535919_3 | SOURCEANDSINK | 3320.001.01 Brannslokking Sprinkler våt 248
Port_5535944_0 | SOURCEANDSINK | 3320.001.01 Brannslokking Sprinkler våt 248
Port_5535971_2 | SOURCEANDSINK | 3320.001.01 Brannslokking Sprinkler våt 248
Port_5535944_1 | SOURCEANDSINK | 3320.001.01 Brannslokking Sprinkler våt 248
Port_5535973_1 | SOURCEANDSINK | 3320.001.01 Brannslokking Sprinkler våt 248
Port_5536021_0 | SOURCEANDSINK | 3320.001.01 Brannslokking Sprinkler våt 249
Port_5536021_1 | SOURCEANDSINK | 3320.001.01 Brannslokking Sprinkler våt 249
Port_5536037_2 | SOURCEANDSINK | 3320.001.01 Brannslokking Sprinkler våt 249
Port_5536037_1 | SOURCEANDSINK | 3320.001.01 Brannslokking Sprinkler våt 249
Port_5536283_0 | SOURCEANDSINK | 3320.001.01 Brannslokking Sprinkler våt 249
Port_5536283_1 | SOURCEANDSINK | 3320.001.01 Brannslokking Sprinkler våt 249
Port_5536285_5 | SOURCEANDSINK | 3320.001.01 Brannslokking Sprinkler våt 249
Port_5536285_1 | SOURCEANDSINK | 3320.001.01 Brannslokking Sprinkler våt 249
Port_5536298_1 | SOURCEANDSINK | 3320.001.01 Brannslokking Sprinkler våt 249
Port_5536285_3 | SOURCEANDSINK | 3320.001.01 Brannslokking Sprinkler våt 249
Port_5537195_1 | SOURCEANDSINK | 3320.001.01 Brannslokking Sprinkler våt 249
Port_5536285_4 | SOURCEANDSINK | 3320.001.01 Brannslokking Sprinkler våt 249
Port_5536651_0 | SOURCEANDSINK | 3320.001.01 Brannslokking Sprinkler våt 249
Port_5536298_2 | SOURCEANDSINK | 3320.001.01 Brannslokking Sprinkler våt 249
Port_5536661_2 | SOURCEANDSINK | 3320.001.01 Brannslokking Sprinkler våt 249
Port_5536558_0 | SOURCEANDSINK | 3320.001.01 Brannslokking Sprinkler våt 249
Port_5536650_4 | SOURCEANDSINK | 3320.001.01 Brannslokking Sprinkler våt 249
Port_5536558_1 | SOURCEANDSINK | 3320.001.01 Brannslokking Sprinkler våt 249
Port_5536661_1 | SOURCEANDSINK | 3320.001.01 Brannslokking Sprinkler våt 249
Port_5536573_0 | SOURCEANDSINK | 3320.001.01 Brannslokking Sprinkler våt 249
Port_5536877_1 | SOURCEANDSINK | 3320.001.01 Brannslokking Sprinkler våt 249
Port_5536573_1 | SOURCEANDSINK | 3320.001.01 Brannslokking Sprinkler våt 249
Port_5536887_2 | SOURCEANDSINK | 3320.001.01 Brannslokking Sprinkler våt 249
Port_5536650_2 | SOURCEANDSINK | 3320.001.01 Brannslokking Sprinkler våt 249
Port_5536887_1 | SOURCEANDSINK | 3320.001.01 Brannslokking Sprinkler våt 249
Port_5536650_3 | SOURCEANDSINK | 3320.001.01 Brannslokking Sprinkler våt 249
Port_5536651_1 | SOURCEANDSINK | 3320.001.01 Brannslokking Sprinkler våt 249
InPort_5536731_1 | SINK | 3320.001.01 Brannslokking Sprinkler våt 249
OutPort_5536830_1 | SOURCE | 3320.001.01 Brannslokking Sprinkler våt 249
Port_5536816_0 | SOURCEANDSINK | 3320.001.01 Brannslokking Sprinkler våt 249
Port_5537195_2 | SOURCEANDSINK | 3320.001.01 Brannslokking Sprinkler våt 249
Port_5536816_1 | SOURCEANDSINK | 3320.001.01 Brannslokking Sprinkler våt 249
Port_5536830_2 | SOURCEANDSINK | 3320.001.01 Brannslokking Sprinkler våt 249
InPort_5536855_1 | SINK | 3320.001.01 Brannslokking Sprinkler våt 249
OutPort_5536858_1 | SOURCE | 3320.001.01 Brannslokking Sprinkler våt 249
Port_5536856_0 | SOURCEANDSINK | 3320.001.01 Brannslokking Sprinkler våt 249
Port_5536858_2 | SOURCEANDSINK | 3320.001.01 Brannslokking Sprinkler våt 249
Port_5536856_1 | SOURCEANDSINK | 3320.001.01 Brannslokking Sprinkler våt 249
Port_5536877_2 | SOURCEANDSINK | 3320.001.01 Brannslokking Sprinkler våt 249
InPort_5537030_1 | SINK | 3320.001.01 Brannslokking Sprinkler våt 253
OutPort_5537037_1 | SOURCE | 3320.001.01 Brannslokking Sprinkler våt 253
Port_5537033_0 | SOURCEANDSINK | 3320.001.01 Brannslokking Sprinkler våt 253
Port_5537033_1 | SOURCEANDSINK | 3320.001.01 Brannslokking Sprinkler våt 253
Port_5537037_2 | SOURCEANDSINK | 3320.001.01 Brannslokking Sprinkler våt 253
Port_5537292_1 | SOURCEANDSINK | 3320.001.01 Brannslokking Sprinkler våt 252
Port_5537294_1 | SOURCEANDSINK | 3320.001.01 Brannslokking Sprinkler våt 252
Port_5537292_3 | SOURCEANDSINK | 3320.001.01 Brannslokking Sprinkler våt 252
Port_5537310_1 | SOURCEANDSINK | 3320.001.01 Brannslokking Sprinkler våt 252
Port_5537292_4 | SOURCEANDSINK | 3320.001.01 Brannslokking Sprinkler våt 252
Port_5537627_0 | SOURCEANDSINK | 3320.001.01 Brannslokking Sprinkler våt 252
Port_5537292_5 | SOURCEANDSINK | 3320.001.01 Brannslokking Sprinkler våt 252
Port_5537357_0 | SOURCEANDSINK | 3320.001.01 Brannslokking Sprinkler våt 252
Port_5537294_2 | SOURCEANDSINK | 3320.001.01 Brannslokking Sprinkler våt 252
InPort_5537305_1 | SINK | 3320.001.01 Brannslokking Sprinkler våt 252
OutPort_5537308_1 | SOURCE | 3320.001.01 Brannslokking Sprinkler våt 252
Port_5537306_0 | SOURCEANDSINK | 3320.001.01 Brannslokking Sprinkler våt 252
Port_5537310_2 | SOURCEANDSINK | 3320.001.01 Brannslokking Sprinkler våt 252
Port_5537306_1 | SOURCEANDSINK | 3320.001.01 Brannslokking Sprinkler våt 252
Port_5537308_2 | SOURCEANDSINK | 3320.001.01 Brannslokking Sprinkler våt 252
Port_5537357_1 | SOURCEANDSINK | 3320.001.01 Brannslokking Sprinkler våt 252
Port_5537377_1 | SOURCEANDSINK | 3320.001.01 Brannslokking Sprinkler våt 252
Port_5537637_2 | SOURCEANDSINK | 3320.001.01 Brannslokking Sprinkler våt 252
Port_5537497_0 | SOURCEANDSINK | 3320.001.01 Brannslokking Sprinkler våt 252
Port_5537626_4 | SOURCEANDSINK | 3320.001.01 Brannslokking Sprinkler våt 252
Port_5537497_1 | SOURCEANDSINK | 3320.001.01 Brannslokking Sprinkler våt 252
Port_5537637_1 | SOURCEANDSINK | 3320.001.01 Brannslokking Sprinkler våt 252
Port_5537626_2 | SOURCEANDSINK | 3320.001.01 Brannslokking Sprinkler våt 252
Port_5537768_0 | SOURCEANDSINK | 3320.001.01 Brannslokking Sprinkler våt 252
Port_5537626_3 | SOURCEANDSINK | 3320.001.01 Brannslokking Sprinkler våt 252
Port_5537627_1 | SOURCEANDSINK | 3320.001.01 Brannslokking Sprinkler våt 252
InPort_5537660_1 | SINK | 3320.001.01 Brannslokking Sprinkler våt 252
OutPort_5537775_2 | SOURCE | 3320.001.01 Brannslokking Sprinkler våt 252
Port_5537661_0 | SOURCEANDSINK | 3320.001.01 Brannslokking Sprinkler våt 252
Port_5537767_4 | SOURCEANDSINK | 3320.001.01 Brannslokking Sprinkler våt 252
Port_5537661_1 | SOURCEANDSINK | 3320.001.01 Brannslokking Sprinkler våt 252
Port_5537775_1 | SOURCEANDSINK | 3320.001.01 Brannslokking Sprinkler våt 252
Port_5537767_2 | SOURCEANDSINK | 3320.001.01 Brannslokking Sprinkler våt 252
Port_5537969_0 | SOURCEANDSINK | 3320.001.01 Brannslokking Sprinkler våt 252
Port_5537767_3 | SOURCEANDSINK | 3320.001.01 Brannslokking Sprinkler våt 252
Port_5537768_1 | SOURCEANDSINK | 3320.001.01 Brannslokking Sprinkler våt 252
InPort_5537795_1 | SINK | 3320.001.01 Brannslokking Sprinkler våt 252
OutPort_5537885_2 | SOURCE | 3320.001.01 Brannslokking Sprinkler våt 252
Port_5537796_0 | SOURCEANDSINK | 3320.001.01 Brannslokking Sprinkler våt 252
Port_5537877_4 | SOURCEANDSINK | 3320.001.01 Brannslokking Sprinkler våt 252
Port_5537796_1 | SOURCEANDSINK | 3320.001.01 Brannslokking Sprinkler våt 252
Port_5537885_1 | SOURCEANDSINK | 3320.001.01 Brannslokking Sprinkler våt 252
Port_5537835_0 | SOURCEANDSINK | 3320.001.01 Brannslokking Sprinkler våt 252
Port_5537944_2 | SOURCEANDSINK | 3320.001.01 Brannslokking Sprinkler våt 252
Port_5537835_1 | SOURCEANDSINK | 3320.001.01 Brannslokking Sprinkler våt 252
Port_5537949_2 | SOURCEANDSINK | 3320.001.01 Brannslokking Sprinkler våt 252
Port_5537877_2 | SOURCEANDSINK | 3320.001.01 Brannslokking Sprinkler våt 252
Port_5537944_1 | SOURCEANDSINK | 3320.001.01 Brannslokking Sprinkler våt 252
Port_5537877_3 | SOURCEANDSINK | 3320.001.01 Brannslokking Sprinkler våt 252
Port_5537878_1 | SOURCEANDSINK | 3320.001.01 Brannslokking Sprinkler våt 252
Port_5537878_0 | SOURCEANDSINK | 3320.001.01 Brannslokking Sprinkler våt 252
Port_5537968_2 | SOURCEANDSINK | 3320.001.01 Brannslokking Sprinkler våt 252
Port_5537976_2 | SOURCEANDSINK | 3320.001.01 Brannslokking Sprinkler våt 252
Port_5537900_0 | SOURCEANDSINK | 3320.001.01 Brannslokking Sprinkler våt 252
Port_5537968_4 | SOURCEANDSINK | 3320.001.01 Brannslokking Sprinkler våt 252
Port_5537900_1 | SOURCEANDSINK | 3320.001.01 Brannslokking Sprinkler våt 252
Port_5537976_1 | SOURCEANDSINK | 3320.001.01 Brannslokking Sprinkler våt 252
Port_5537913_0 | SOURCEANDSINK | 3320.001.01 Brannslokking Sprinkler våt 252
Port_5537913_1 | SOURCEANDSINK | 3320.001.01 Brannslokking Sprinkler våt 252
Port_5537951_2 | SOURCEANDSINK | 3320.001.01 Brannslokking Sprinkler våt 252
Port_5537918_0 | SOURCEANDSINK | 3320.001.01 Brannslokking Sprinkler våt 252
Port_5537949_1 | SOURCEANDSINK | 3320.001.01 Brannslokking Sprinkler våt 252
Port_5537918_1 | SOURCEANDSINK | 3320.001.01 Brannslokking Sprinkler våt 252
Port_5537951_1 | SOURCEANDSINK | 3320.001.01 Brannslokking Sprinkler våt 252
Port_5537968_3 | SOURCEANDSINK | 3320.001.01 Brannslokking Sprinkler våt 252
Port_5537969_1 | SOURCEANDSINK | 3320.001.01 Brannslokking Sprinkler våt 252
InPort_5538061_1 | SINK | 3320.001.01 Brannslokking Sprinkler våt 253
OutPort_5538064_1 | SOURCE | 3320.001.01 Brannslokking Sprinkler våt 253
Port_5538062_0 | SOURCEANDSINK | 3320.001.01 Brannslokking Sprinkler våt 253
Port_5538062_1 | SOURCEANDSINK | 3320.001.01 Brannslokking Sprinkler våt 253
Port_5538064_2 | SOURCEANDSINK | 3320.001.01 Brannslokking Sprinkler våt 253
Port_5538231_2 | SOURCEANDSINK | 3320.001.01 Brannslokking Sprinkler våt 2
Port_5541437_0 | SOURCEANDSINK | 3320.001.01 Brannslokking Sprinkler våt 2
InPort_5538621_1 | SINK | 3320.001.01 Brannslokking Sprinkler våt 167
OutPort_5538630_2 | SOURCE | 3320.001.01 Brannslokking Sprinkler våt 167
Port_5538622_0 | SOURCEANDSINK | 3320.001.01 Brannslokking Sprinkler våt 167
Port_5538622_1 | SOURCEANDSINK | 3320.001.01 Brannslokking Sprinkler våt 167
Port_5538630_1 | SOURCEANDSINK | 3320.001.01 Brannslokking Sprinkler våt 167
InPort_5538925_1 | SINK | 3320.001.01 Brannslokking Sprinkler våt 167
OutPort_5538928_1 | SOURCE | 3320.001.01 Brannslokking Sprinkler våt 167
Port_5538926_0 | SOURCEANDSINK | 3320.001.01 Brannslokking Sprinkler våt 167
Port_5538926_1 | SOURCEANDSINK | 3320.001.01 Brannslokking Sprinkler våt 167
Port_5538928_2 | SOURCEANDSINK | 3320.001.01 Brannslokking Sprinkler våt 167
InPort_5539471_1 | SINK | 3320.001.01 Brannslokking Sprinkler våt 167
OutPort_5539476_2 | SOURCE | 3320.001.01 Brannslokking Sprinkler våt 167
Port_5539472_0 | SOURCEANDSINK | 3320.001.01 Brannslokking Sprinkler våt 167
Port_5539472_1 | SOURCEANDSINK | 3320.001.01 Brannslokking Sprinkler våt 167
Port_5539476_1 | SOURCEANDSINK | 3320.001.01 Brannslokking Sprinkler våt 167
InPort_5539614_1 | SINK | 3320.001.01 Brannslokking Sprinkler våt 167
OutPort_5539619_2 | SOURCE | 3320.001.01 Brannslokking Sprinkler våt 167
Port_5539615_0 | SOURCEANDSINK | 3320.001.01 Brannslokking Sprinkler våt 167
Port_5539615_1 | SOURCEANDSINK | 3320.001.01 Brannslokking Sprinkler våt 167
Port_5539619_1 | SOURCEANDSINK | 3320.001.01 Brannslokking Sprinkler våt 167
Port_5539961_0 | SOURCEANDSINK | 3320.001.01 Brannslokking Sprinkler våt 255
Port_5539963_2 | SOURCEANDSINK | 3320.001.01 Brannslokking Sprinkler våt 255
Port_5539961_1 | SOURCEANDSINK | 3320.001.01 Brannslokking Sprinkler våt 255
Port_5539966_2 | SOURCEANDSINK | 3320.001.01 Brannslokking Sprinkler våt 255
Port_5539963_1 | SOURCEANDSINK | 3320.001.01 Brannslokking Sprinkler våt 255
Port_5539965_1 | SOURCEANDSINK | 3320.001.01 Brannslokking Sprinkler våt 255
InPort_5539965_1 | SINK | 3320.001.01 Brannslokking Sprinkler våt 255
OutPort_5539963_1 | SOURCE | 3320.001.01 Brannslokking Sprinkler våt 255
Port_5539966_1 | SOURCEANDSINK | 3320.001.01 Brannslokking Sprinkler våt 255
Port_5540024_1 | SOURCEANDSINK | 3320.001.01 Brannslokking Sprinkler våt 255
Port_5540024_2 | SOURCEANDSINK | 3320.001.01 Brannslokking Sprinkler våt 255
Port_5540146_0 | SOURCEANDSINK | 3320.001.01 Brannslokking Sprinkler våt 255
Port_5540057_0 | SOURCEANDSINK | 3320.001.01 Brannslokking Sprinkler våt 255
Port_5540145_4 | SOURCEANDSINK | 3320.001.01 Brannslokking Sprinkler våt 255
Port_5540057_1 | SOURCEANDSINK | 3320.001.01 Brannslokking Sprinkler våt 255
Port_5540153_1 | SOURCEANDSINK | 3320.001.01 Brannslokking Sprinkler våt 255
InPort_5540061_1 | SINK | 3320.001.01 Brannslokking Sprinkler våt 255
OutPort_5540153_2 | SOURCE | 3320.001.01 Brannslokking Sprinkler våt 255
Port_5540071_0 | SOURCEANDSINK | 3320.001.01 Brannslokking Sprinkler våt 255
Port_5540155_4 | SOURCEANDSINK | 3320.001.01 Brannslokking Sprinkler våt 255
Port_5540071_1 | SOURCEANDSINK | 3320.001.01 Brannslokking Sprinkler våt 255
Port_5540163_1 | SOURCEANDSINK | 3320.001.01 Brannslokking Sprinkler våt 255
InPort_5540075_1 | SINK | 3320.001.01 Brannslokking Sprinkler våt 255
OutPort_5540163_2 | SOURCE | 3320.001.01 Brannslokking Sprinkler våt 255
Port_5540145_2 | SOURCEANDSINK | 3320.001.01 Brannslokking Sprinkler våt 255
Port_5540156_0 | SOURCEANDSINK | 3320.001.01 Brannslokking Sprinkler våt 255
Port_5540145_3 | SOURCEANDSINK | 3320.001.01 Brannslokking Sprinkler våt 255
Port_5540146_1 | SOURCEANDSINK | 3320.001.01 Brannslokking Sprinkler våt 255
Port_5540155_2 | SOURCEANDSINK | 3320.001.01 Brannslokking Sprinkler våt 255
Port_5540409_1 | SOURCEANDSINK | 3320.001.01 Brannslokking Sprinkler våt 255
Port_5540155_3 | SOURCEANDSINK | 3320.001.01 Brannslokking Sprinkler våt 255
Port_5540156_1 | SOURCEANDSINK | 3320.001.01 Brannslokking Sprinkler våt 255
Port_5540327_0 | SOURCEANDSINK | 3320.001.01 Brannslokking Sprinkler våt 255
Port_5540330_4 | SOURCEANDSINK | 3320.001.01 Brannslokking Sprinkler våt 255
Port_5540327_1 | SOURCEANDSINK | 3320.001.01 Brannslokking Sprinkler våt 255
Port_5540332_1 | SOURCEANDSINK | 3320.001.01 Brannslokking Sprinkler våt 255
InPort_5540329_1 | SINK | 3320.001.01 Brannslokking Sprinkler våt 255
OutPort_5540332_2 | SOURCE | 3320.001.01 Brannslokking Sprinkler våt 255
Port_5540330_2 | SOURCEANDSINK | 3320.001.01 Brannslokking Sprinkler våt 255
Port_5540421_0 | SOURCEANDSINK | 3320.001.01 Brannslokking Sprinkler våt 255
Port_5540330_3 | SOURCEANDSINK | 3320.001.01 Brannslokking Sprinkler våt 255
Port_5540409_0 | SOURCEANDSINK | 3320.001.01 Brannslokking Sprinkler våt 255
Port_5540421_1 | SOURCEANDSINK | 3320.001.01 Brannslokking Sprinkler våt 255
Port_5540451_4 | SOURCEANDSINK | 3320.001.01 Brannslokking Sprinkler våt 255
Port_5540431_0 | SOURCEANDSINK | 3320.001.01 Brannslokking Sprinkler våt 255
Port_5540451_2 | SOURCEANDSINK | 3320.001.01 Brannslokking Sprinkler våt 255
Port_5540431_1 | SOURCEANDSINK | 3320.001.01 Brannslokking Sprinkler våt 255
Port_5541408_1 | SOURCEANDSINK | 3320.001.01 Brannslokking Sprinkler våt 255
Port_5540451_3 | SOURCEANDSINK | 3320.001.01 Brannslokking Sprinkler våt 255
Port_5540742_0 | SOURCEANDSINK | 3320.001.01 Brannslokking Sprinkler våt 255
Port_5540486_0 | SOURCEANDSINK | 3320.001.01 Brannslokking Sprinkler våt 255
Port_5540489_4 | SOURCEANDSINK | 3320.001.01 Brannslokking Sprinkler våt 255
Port_5540486_1 | SOURCEANDSINK | 3320.001.01 Brannslokking Sprinkler våt 255
Port_5540491_1 | SOURCEANDSINK | 3320.001.01 Brannslokking Sprinkler våt 255
InPort_5540488_1 | SINK | 3320.001.01 Brannslokking Sprinkler våt 255
OutPort_5540491_2 | SOURCE | 3320.001.01 Brannslokking Sprinkler våt 255
Port_5540489_2 | SOURCEANDSINK | 3320.001.01 Brannslokking Sprinkler våt 255
Port_5540500_1 | SOURCEANDSINK | 3320.001.01 Brannslokking Sprinkler våt 255
Port_5540489_3 | SOURCEANDSINK | 3320.001.01 Brannslokking Sprinkler våt 255
Port_5540642_2 | SOURCEANDSINK | 3320.001.01 Brannslokking Sprinkler våt 255
Port_5540493_0 | SOURCEANDSINK | 3320.001.01 Brannslokking Sprinkler våt 255
Port_5540496_4 | SOURCEANDSINK | 3320.001.01 Brannslokking Sprinkler våt 255
Port_5540493_1 | SOURCEANDSINK | 3320.001.01 Brannslokking Sprinkler våt 255
Port_5540498_1 | SOURCEANDSINK | 3320.001.01 Brannslokking Sprinkler våt 255
InPort_5540495_1 | SINK | 3320.001.01 Brannslokking Sprinkler våt 255
OutPort_5540498_2 | SOURCE | 3320.001.01 Brannslokking Sprinkler våt 255
Port_5540496_2 | SOURCEANDSINK | 3320.001.01 Brannslokking Sprinkler våt 255
Port_5540587_0 | SOURCEANDSINK | 3320.001.01 Brannslokking Sprinkler våt 255
Port_5540496_3 | SOURCEANDSINK | 3320.001.01 Brannslokking Sprinkler våt 255
Port_5540500_0 | SOURCEANDSINK | 3320.001.01 Brannslokking Sprinkler våt 255
Port_5540527_0 | SOURCEANDSINK | 3320.001.01 Brannslokking Sprinkler våt 255
Port_5540637_2 | SOURCEANDSINK | 3320.001.01 Brannslokking Sprinkler våt 255
Port_5540527_1 | SOURCEANDSINK | 3320.001.01 Brannslokking Sprinkler våt 255
Port_5540532_1 | SOURCEANDSINK | 3320.001.01 Brannslokking Sprinkler våt 255
InPort_5540529_1 | SINK | 3320.001.01 Brannslokking Sprinkler våt 255
OutPort_5540532_2 | SOURCE | 3320.001.01 Brannslokking Sprinkler våt 255
Port_5540577_0 | SOURCEANDSINK | 3320.001.01 Brannslokking Sprinkler våt 255
Port_5540744_4 | SOURCEANDSINK | 3320.001.01 Brannslokking Sprinkler våt 255
Port_5540577_1 | SOURCEANDSINK | 3320.001.01 Brannslokking Sprinkler våt 255
Port_5540599_2 | SOURCEANDSINK | 3320.001.01 Brannslokking Sprinkler våt 255
Port_5540587_1 | SOURCEANDSINK | 3320.001.01 Brannslokking Sprinkler våt 255
Port_5540599_1 | SOURCEANDSINK | 3320.001.01 Brannslokking Sprinkler våt 255
Port_5540601_0 | SOURCEANDSINK | 3320.001.01 Brannslokking Sprinkler våt 255
Port_5540637_1 | SOURCEANDSINK | 3320.001.01 Brannslokking Sprinkler våt 255
Port_5540601_1 | SOURCEANDSINK | 3320.001.01 Brannslokking Sprinkler våt 255
Port_5540642_1 | SOURCEANDSINK | 3320.001.01 Brannslokking Sprinkler våt 255
InPort_5540665_1 | SINK | 3320.001.01 Brannslokking Sprinkler våt 255
OutPort_5541257_1 | SOURCE | 3320.001.01 Brannslokking Sprinkler våt 255
Port_5540882_2 | SOURCEANDSINK | 3320.001.01 Brannslokking Sprinkler våt 255
Port_5540703_0 | SOURCEANDSINK | 3320.001.01 Brannslokking Sprinkler våt 255
Port_5540874_4 | SOURCEANDSINK | 3320.001.01 Brannslokking Sprinkler våt 255
Port_5540703_1 | SOURCEANDSINK | 3320.001.01 Brannslokking Sprinkler våt 255
Port_5540882_1 | SOURCEANDSINK | 3320.001.01 Brannslokking Sprinkler våt 255
Port_5540740_0 | SOURCEANDSINK | 3320.001.01 Brannslokking Sprinkler våt 255
Port_5540740_1 | SOURCEANDSINK | 3320.001.01 Brannslokking Sprinkler våt 255
Port_5540744_3 | SOURCEANDSINK | 3320.001.01 Brannslokking Sprinkler våt 255
Port_5540742_1 | SOURCEANDSINK | 3320.001.01 Brannslokking Sprinkler våt 255
Port_5540744_5 | SOURCEANDSINK | 3320.001.01 Brannslokking Sprinkler våt 255
Port_5540744_1 | SOURCEANDSINK | 3320.001.01 Brannslokking Sprinkler våt 255
Port_5540875_0 | SOURCEANDSINK | 3320.001.01 Brannslokking Sprinkler våt 255
Port_5540746_0 | SOURCEANDSINK | 3320.001.01 Brannslokking Sprinkler våt 255
Port_5541259_1 | SOURCEANDSINK | 3320.001.01 Brannslokking Sprinkler våt 255
Port_5540746_1 | SOURCEANDSINK | 3320.001.01 Brannslokking Sprinkler våt 255
Port_5541263_1 | SOURCEANDSINK | 3320.001.01 Brannslokking Sprinkler våt 255
Port_5540874_2 | SOURCEANDSINK | 3320.001.01 Brannslokking Sprinkler våt 255
Port_5541263_2 | SOURCEANDSINK | 3320.001.01 Brannslokking Sprinkler våt 255
Port_5540874_3 | SOURCEANDSINK | 3320.001.01 Brannslokking Sprinkler våt 255
Port_5540875_1 | SOURCEANDSINK | 3320.001.01 Brannslokking Sprinkler våt 255
InPort_5541154_1 | SINK | 3320.001.01 Brannslokking Sprinkler våt 257
OutPort_5541351_2 | SOURCE | 3320.001.01 Brannslokking Sprinkler våt 257
Port_5541227_0 | SOURCEANDSINK | 3320.001.01 Brannslokking Sprinkler våt 255
Port_5541257_2 | SOURCEANDSINK | 3320.001.01 Brannslokking Sprinkler våt 255
Port_5541227_1 | SOURCEANDSINK | 3320.001.01 Brannslokking Sprinkler våt 255
Port_5541259_2 | SOURCEANDSINK | 3320.001.01 Brannslokking Sprinkler våt 255
Port_5541307_0 | SOURCEANDSINK | 3320.001.01 Brannslokking Sprinkler våt 257
Port_5541307_1 | SOURCEANDSINK | 3320.001.01 Brannslokking Sprinkler våt 257
Port_5541351_1 | SOURCEANDSINK | 3320.001.01 Brannslokking Sprinkler våt 257
Port_5541437_1 | SOURCEANDSINK | 3320.001.01 Brannslokking Sprinkler våt 2
InPort_5543282_1 | SINK | 3320.001.01 Brannslokking Sprinkler våt 258
OutPort_5543287_2 | SOURCE | 3320.001.01 Brannslokking Sprinkler våt 258
Port_5543283_0 | SOURCEANDSINK | 3320.001.01 Brannslokking Sprinkler våt 258
Port_5543283_1 | SOURCEANDSINK | 3320.001.01 Brannslokking Sprinkler våt 258
Port_5543287_1 | SOURCEANDSINK | 3320.001.01 Brannslokking Sprinkler våt 258
InPort_5543596_1 | SINK | 3320.001.01 Brannslokking Sprinkler våt 258
OutPort_5543601_2 | SOURCE | 3320.001.01 Brannslokking Sprinkler våt 258
Port_5543601_1 | SOURCEANDSINK | 3320.001.01 Brannslokking Sprinkler våt 258
Port_5543806_0 | SOURCEANDSINK | 3320.001.01 Brannslokking Sprinkler våt 258
Port_5543806_1 | SOURCEANDSINK | 3320.001.01 Brannslokking Sprinkler våt 258
InPort_5544257_1 | SINK | 3320.001.01 Brannslokking Sprinkler våt 258
OutPort_5544262_2 | SOURCE | 3320.001.01 Brannslokking Sprinkler våt 258
Port_5544258_0 | SOURCEANDSINK | 3320.001.01 Brannslokking Sprinkler våt 258
Port_5544258_1 | SOURCEANDSINK | 3320.001.01 Brannslokking Sprinkler våt 258
Port_5544262_1 | SOURCEANDSINK | 3320.001.01 Brannslokking Sprinkler våt 258
InPort_5545533_1 | SINK | 3320.001.01 Brannslokking Sprinkler våt 260
OutPort_5545629_1 | SOURCE | 3320.001.01 Brannslokking Sprinkler våt 260
Port_5545608_0 | SOURCEANDSINK | 3320.001.01 Brannslokking Sprinkler våt 260
Port_5545629_2 | SOURCEANDSINK | 3320.001.01 Brannslokking Sprinkler våt 260
Port_5545608_1 | SOURCEANDSINK | 3320.001.01 Brannslokking Sprinkler våt 260
Port_5632378_1 | SOURCEANDSINK | 3200.00x.xx Varme Radiator Tur 55° 2
Port_5632500_1 | SOURCEANDSINK | 3200.00x.xx Varme Radiator Retur 40° 2
Port_5632344_0 | SOURCEANDSINK | 3200.00x.xx Varme Radiator Tur 55° 2
Port_5632378_2 | SOURCEANDSINK | 3200.00x.xx Varme Radiator Tur 55° 2
Port_5632344_1 | SOURCEANDSINK | 3200.00x.xx Varme Radiator Tur 55° 2
Port_5632527_1 | SOURCEANDSINK | 3200.00x.xx Varme Radiator Tur 55° 2
Port_5632393_0 | SOURCEANDSINK | 3200.00x.xx Varme Radiator Retur 40° 2
Port_5632500_2 | SOURCEANDSINK | 3200.00x.xx Varme Radiator Retur 40° 2
Port_5632393_1 | SOURCEANDSINK | 3200.00x.xx Varme Radiator Retur 40° 2
Port_5632523_1 | SOURCEANDSINK | 3200.00x.xx Varme Radiator Retur 40° 2
Port_5632520_0 | SOURCEANDSINK | 3200.00x.xx Varme Radiator Retur 40° 2
Port_5632523_2 | SOURCEANDSINK | 3200.00x.xx Varme Radiator Retur 40° 2
Port_5632520_1 | SOURCEANDSINK | 3200.00x.xx Varme Radiator Retur 40° 2
Port_5632524_0 | SOURCEANDSINK | 3200.00x.xx Varme Radiator Tur 55° 2
Port_5632527_2 | SOURCEANDSINK | 3200.00x.xx Varme Radiator Tur 55° 2
Port_5632524_1 | SOURCEANDSINK | 3200.00x.xx Varme Radiator Tur 55° 2
Port_5652193_1 | SOURCEANDSINK | 3200.00x.xx Varme Retur 35° 1
Port_5652196_1 | SOURCEANDSINK | 3200.00x.xx Varme Tur 55° 1
Port_5639864_1 | SOURCEANDSINK | 3200.00x.xx Varme Radiator Retur 40° 7
Port_5639856_0 | SOURCEANDSINK | 3200.00x.xx Varme Radiator Retur 40° 7
Port_5639864_2 | SOURCEANDSINK | 3200.00x.xx Varme Radiator Retur 40° 7
Port_5639856_1 | SOURCEANDSINK | 3200.00x.xx Varme Radiator Retur 40° 7
Port_5639876_1 | SOURCEANDSINK | 3200.00x.xx Varme Radiator Retur 40° 7
Port_5639876_2 | SOURCEANDSINK | 3200.00x.xx Varme Radiator Retur 40° 7
Port_5652215_1 | SOURCEANDSINK | 3700.001.05 Kjøle Retur 18° 3
Port_5652199_1 | SOURCEANDSINK | 3700.001.04 Kjøle Tur 10° 2
Port_5652215_2 | SOURCEANDSINK | 3700.001.05 Kjøle Retur 18° 3
Port_5652199_2 | SOURCEANDSINK | 3700.001.04 Kjøle Tur 10° 2
Port_5652193_2 | SOURCEANDSINK | 3200.00x.xx Varme Retur 35° 1
Port_5652196_2 | SOURCEANDSINK | 3200.00x.xx Varme Tur 55° 1

# IfcDoor: IGD Tofløyet Glass:IGD Tofløyet Glass, IGD Tofløyet Glass:IGD Tofløyet Glass:12530859
In: H02-Nivå F-3,5 m
Type - OperationType: DOUBLE_DOOR_SINGLE_SWING; ParameterTakesPrecedence: no; Sizeable: no; Material: Metal brushed, Glass, Panel white
Type - IfcDoorPanelProperties - PanelOperation: SWINGING
OverallHeight: 2200 mm; OverallWidth: 2178.52 mm; Classification: B2030100 Glazed Doors & Entrances (Uniformat)
ePset_Simplebim - Assembly Level: Leaf
ePset_LocationTool - Splitting: ORIGINAL
Pset_DoorCommon - Reference: IGD Tofløyet Glass:IGD Tofløyet Glass
ePset_SimplebimBasicQuantities - Length, frame (Simplebim): 6578.5 mm; Width (Simplebim): 2178.5 mm; Area (Simplebim): 4.7927 m2; Height (Simplebim): 2200 mm

# IfcDoor: NSW Innvendig slagdør, enkel:8M x 21M, NSW Innvendig slagdør, enkel:8M x 21M:11871248
In: H02-Nivå F-3,5 m
Type - ParameterTakesPrecedence: no; Sizeable: no; Material: <Unnamed>, _NSW Dør - dørblad, hvit, _NSW Dør - terskel, tre, _NSW Dør - listverk, hvit
OverallHeight: 2100 mm; OverallWidth: 810 mm
ePset_SimplebimBasicQuantities - Width (Simplebim): 867 mm; Width, opening (Simplebim): 810 mm; Area, opening (Simplebim): 1.701 m2; Area (Simplebim): 1.84541 m2; Height, opening (Simplebim): 2100 mm; Height (Simplebim): 2128.5 mm; Length, frame (Simplebim): 5124 mm
ePset_Simplebim - Assembly Level: Leaf
AVINOR - 05_ID-nummer: +BR001=244.02084
Pset_DoorCommon - Reference: NSW Innvendig slagdør, enkel:8M x 21M
ePset_LocationTool - Splitting: ORIGINAL

# IfcDoor: NSW Innvendig slagdør, enkel:ID-10M x 21M (2)
In: H02-Nivå F-3,5 m
Type - ParameterTakesPrecedence: no; Sizeable: no; Material: <Unnamed>, _NSW Dør - dørblad, hvit, _NSW Dør - terskel, tre, _NSW Dør - listverk, hvit
OverallHeight: 2100 mm; OverallWidth: 1010 mm
Pset_DoorCommon - Reference: NSW Innvendig slagdør, enkel:ID-10M x 21M
ePset_Simplebim - Assembly Level: Leaf
ePset_LocationTool - Splitting: ORIGINAL
ePset_SimplebimBasicQuantities - Area, opening (Simplebim): 2.121 m2; Width (Simplebim): 1067 mm; Width, opening (Simplebim): 1010 mm; Area (Simplebim): 2.27111 m2; Height, opening (Simplebim): 2100 mm; Height (Simplebim): 2128.5 mm; Length, frame (Simplebim): 5324 mm
Name (NSW Innvendig slagdør, enkel:ID-10M x 21M:...)
11871247 | AVINOR - 05_ID-nummer: +BR001=244.02085
12075870

# IfcFlowController: BALL-VALVE-THREAD:ball-valve-thead-DN15 (2)
In: H01-Nivå D+0,36
Type - Material: 3200.002 Retur
ePset_Simplebim - Assembly Level: Leaf
ePset_LocationTool - Splitting: ORIGINAL
Name (BALL-VALVE-THREAD:ball-valve-thead-DN15:...) | Group
5632523 | 3200.00x.xx Varme Radiator Retur 40° 2
5632527 | 3200.00x.xx Varme Radiator Tur 55° 2

# IfcFlowFitting: Bend sveist:EN 10253-1 S235 3D ISO (7)
In: H01-Nivå D+0,36
Type - Material: 3320.001
ePset_Simplebim - Assembly Level: Leaf
Name (Bend sveist:EN 10253-1 S235 3D ISO:...) | Splitting | Group
5534892 | ORIGINAL | 3320.001.01 Brannslokking Sprinkler våt 2
5534904 | ORIGINAL | 3320.001.01 Brannslokking Sprinkler våt 2
5534918 | ORIGINAL | 3320.001.01 Brannslokking Sprinkler våt 2
5534930 | ORIGINAL | 3320.001.01 Brannslokking Sprinkler våt 2
5652199 | ORIGINAL | 3700.001.04 Kjøle Tur 10° 2
5652215 | ORIGINAL | 3700.001.05 Kjøle Retur 18° 3
5541488 | RESULT | 3320.001.01 Brannslokking Sprinkler våt 2

# IfcFlowFitting: Lindab ESU:ESU (9)
In: H01-Nivå D+0,36
Type - Material: DF_Material1
ePset_Simplebim - Assembly Level: Leaf
ePset_LocationTool - Splitting: ORIGINAL
Name (Lindab ESU:ESU:...) | Group
5470001 | 36.03 Tilluft 1.etg nord og øst + nordfløy: 1
5470053 | 36.03 Tilluft 1.etg nord og øst + nordfløy: 1
5472456 | 36.03 Tilluft 1.etg nord og øst + nordfløy: 1
5472611 | 36.03 Tilluft 1.etg nord og øst + nordfløy: 1
5473337 | 36.03 Tilluft 1.etg nord og øst + nordfløy: 1
5480765 | 36.03 Avtrekk 1.etg nord og øst + nordfløy: 1
5481084 | 36.03 Avtrekk 1.etg nord og øst + nordfløy: 1
5482213 | 36.03 Avtrekk 1.etg nord og øst + nordfløy: 1
5483604 | 36.03 Avtrekk 1.etg nord og øst + nordfløy: 1

# IfcFlowFitting: Lindab TCPU:TCPU (21)
In: H01-Nivå D+0,36
Type - Material: DF_Material1
ePset_Simplebim - Assembly Level: Leaf
Name (Lindab TCPU:TCPU:...) | Splitting | Group
5469910 | ORIGINAL | 36.03 Tilluft 1.etg nord og øst + nordfløy: 1
5470047 | ORIGINAL | 36.03 Tilluft 1.etg nord og øst + nordfløy: 1
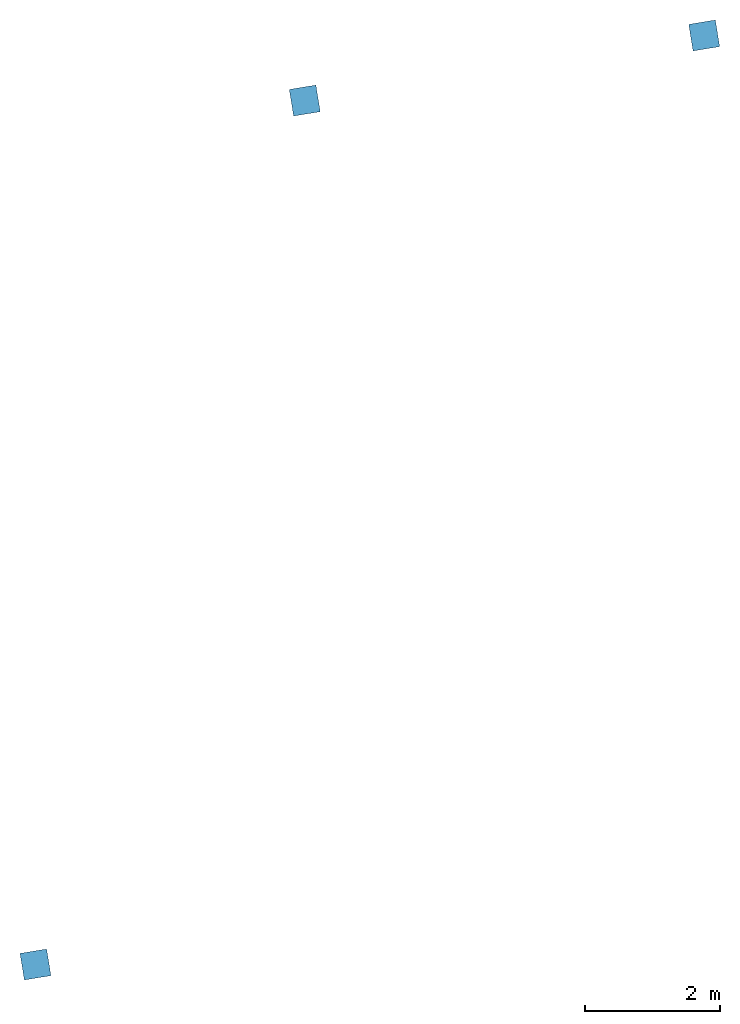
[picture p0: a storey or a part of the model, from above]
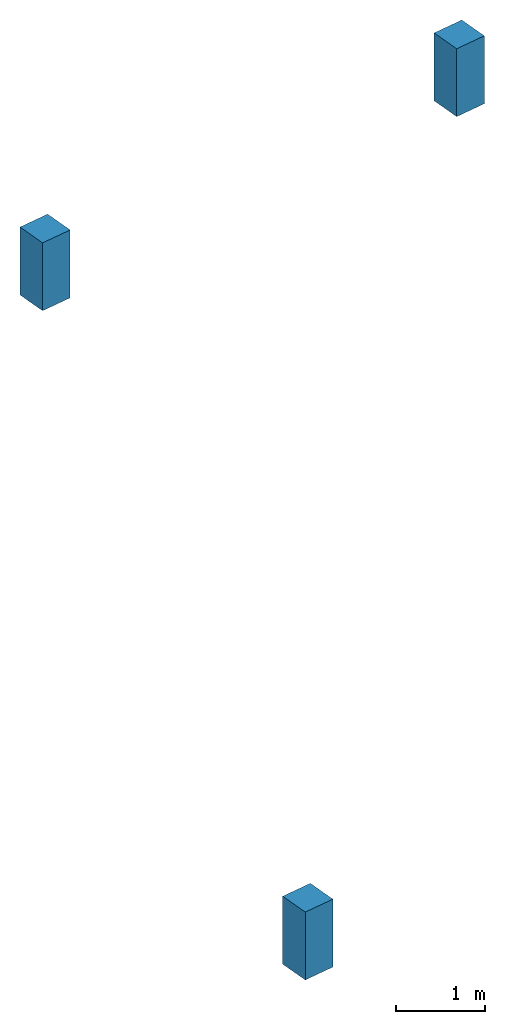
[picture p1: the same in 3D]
Properties of the parts of a building model (IFC2X3), part 2 of 2

# IfcFlowFitting: Lindab TCPU:TCPU (21)
Name (Lindab TCPU:TCPU:...) | Splitting | Group
5470427 | ORIGINAL | 36.03 Tilluft 1.etg nord og øst + nordfløy: 1
5472323 | ORIGINAL | 36.03 Tilluft 1.etg nord og øst + nordfløy: 1
5472331 | ORIGINAL | 36.03 Tilluft 1.etg nord og øst + nordfløy: 1
5472339 | ORIGINAL | 36.03 Tilluft 1.etg nord og øst + nordfløy: 1
5472593 | ORIGINAL | 36.03 Tilluft 1.etg nord og øst + nordfløy: 1
5472601 | ORIGINAL | 36.03 Tilluft 1.etg nord og øst + nordfløy: 1
5480925 | ORIGINAL | 36.03 Avtrekk 1.etg nord og øst + nordfløy: 1
5480973 | ORIGINAL | 36.03 Avtrekk 1.etg nord og øst + nordfløy: 1
5480989 | ORIGINAL | 36.03 Avtrekk 1.etg nord og øst + nordfløy: 1
5481543 | ORIGINAL | 36.03 Avtrekk 1.etg nord og øst + nordfløy: 1
5481863 | ORIGINAL | 36.03 Avtrekk 1.etg nord og øst + nordfløy: 1
5482037 | ORIGINAL | 36.03 Avtrekk 1.etg nord og øst + nordfløy: 1
5482051 | ORIGINAL | 36.03 Avtrekk 1.etg nord og øst + nordfløy: 1
5482065 | ORIGINAL | 36.03 Avtrekk 1.etg nord og øst + nordfløy: 1
5482079 | ORIGINAL | 36.03 Avtrekk 1.etg nord og øst + nordfløy: 1
5483259 | ORIGINAL | 36.03 Avtrekk 1.etg nord og øst + nordfløy: 1
5483554 | ORIGINAL | 36.03 Avtrekk 1.etg nord og øst + nordfløy: 1
5508675 | ORIGINAL | 36.26 Tilluft Bagasjehall 1.etg: 1
5482023 | RESULT | 36.03 Avtrekk 1.etg nord og øst + nordfløy: 1

# IfcFlowFitting: Overgang Konsentrisk:EN 10253-2 P235GH TC1, Overgang Konsentrisk:EN 10253-2 P235GH TC1:5538231
In: H01-Nivå D+0,36
Type - Material: 3320.001
ePset_LocationTool - Splitting: ORIGINAL
ePset_Simplebim - Assembly Level: Leaf
Group: 3320.001.01 Brannslokking Sprinkler våt 2

# IfcFlowFitting: PRO_103184:DN10-100 / d12-108 - OD (6)
In: H01-Nivå D+0,36
Type - Description: Geberit Mapress El-Forsinket Stål bend; PredefinedType: BEND; Material: Geberit_Plastic_Red, Geberit_Mapress_C-Steel
ePset_LocationTool - Splitting: ORIGINAL
ePset_Simplebim - Assembly Level: Leaf
Name (PRO_103184:DN10-100 / d12-108 - OD:...) | Group
5632378 | 3200.00x.xx Varme Radiator Tur 55° 2
5632500 | 3200.00x.xx Varme Radiator Retur 40° 2
5639864 | 3200.00x.xx Varme Radiator Retur 40° 7
5639876 | 3200.00x.xx Varme Radiator Retur 40° 7
5652193 | 3200.00x.xx Varme Retur 35° 1
5652196 | 3200.00x.xx Varme Tur 55° 1

# IfcFlowFitting: RS_53_PIF_UN_Cross-EN10241_MC_gen:RS_53_PIF_UN_Cross-EN10241_MC_gen (3)
In: H01-Nivå D+0,36
Type - Material: 3320.001
ePset_LocationTool - Splitting: ORIGINAL
ePset_Simplebim - Assembly Level: Leaf
Name (RS_53_PIF_UN_Cross-EN10241_MC_gen:RS_53_PIF_UN_Cross-EN10241_MC_gen:...) | Group
5536285 | 3320.001.01 Brannslokking Sprinkler våt 249
5537292 | 3320.001.01 Brannslokking Sprinkler våt 252
5540744 | 3320.001.01 Brannslokking Sprinkler våt 255

# IfcFlowFitting: RS_53_PIF_UN_Elbow-EN10241_NOR:RS_53_PIF_UN_Elbow-EN10241_NOR (15)
In: H01-Nivå D+0,36
Type - Material: 3320.001
ePset_Simplebim - Assembly Level: Leaf
ePset_LocationTool - Splitting: ORIGINAL
Name (RS_53_PIF_UN_Elbow-EN10241_NOR:RS_53_PIF_UN_Elbow-EN10241_NOR:...) | Group
5535927 | 3320.001.01 Brannslokking Sprinkler våt 248
5535971 | 3320.001.01 Brannslokking Sprinkler våt 248
5535973 | 3320.001.01 Brannslokking Sprinkler våt 248
5536037 | 3320.001.01 Brannslokking Sprinkler våt 249
5536661 | 3320.001.01 Brannslokking Sprinkler våt 249
5536877 | 3320.001.01 Brannslokking Sprinkler våt 249
5537637 | 3320.001.01 Brannslokking Sprinkler våt 252
5537949 | 3320.001.01 Brannslokking Sprinkler våt 252
5537951 | 3320.001.01 Brannslokking Sprinkler våt 252
5537976 | 3320.001.01 Brannslokking Sprinkler våt 252
5539966 | 3320.001.01 Brannslokking Sprinkler våt 255
5540599 | 3320.001.01 Brannslokking Sprinkler våt 255
5540637 | 3320.001.01 Brannslokking Sprinkler våt 255
5540882 | 3320.001.01 Brannslokking Sprinkler våt 255
5541259 | 3320.001.01 Brannslokking Sprinkler våt 255

# IfcFlowFitting: RS_53_PIF_UN_Hexagon-Plug-EN10241_MC_gen:RS_53_PIF_UN_Hexagon-Plug-EN10241_MC_gen (2)
In: H01-Nivå D+0,36
Type - Material: 3320.001
ePset_Simplebim - Assembly Level: Leaf
ePset_LocationTool - Splitting: ORIGINAL
Name (RS_53_PIF_UN_Hexagon-Plug-EN10241_MC_gen:RS_53_PIF_UN_Hexagon-Plug-EN10241_MC_gen:...) | Group
5537377 | 3320.001.01 Brannslokking Sprinkler våt 252
5541408 | 3320.001.01 Brannslokking Sprinkler våt 255

# IfcFlowFitting: RS_53_PIF_UN_Reducing-Socket-EN10241_MC_gen:RS_53_PIF_UN_Reducing-Socket-EN10241_MC_gen (34)
In: H01-Nivå D+0,36
Type - Material: 3320.001
ePset_Simplebim - Assembly Level: Leaf
ePset_LocationTool - Splitting: ORIGINAL
Name (RS_53_PIF_UN_Reducing-Socket-EN10241_MC_gen:RS_53_PIF_UN_Reducing-Socket-EN10241_MC_gen:...) | Group
5535931 | 3320.001.01 Brannslokking Sprinkler våt 248
5536298 | 3320.001.01 Brannslokking Sprinkler våt 249
5536830 | 3320.001.01 Brannslokking Sprinkler våt 249
5536858 | 3320.001.01 Brannslokking Sprinkler våt 249
5536887 | 3320.001.01 Brannslokking Sprinkler våt 249
5537037 | 3320.001.01 Brannslokking Sprinkler våt 253
5537195 | 3320.001.01 Brannslokking Sprinkler våt 249
5537294 | 3320.001.01 Brannslokking Sprinkler våt 252
5537308 | 3320.001.01 Brannslokking Sprinkler våt 252
5537310 | 3320.001.01 Brannslokking Sprinkler våt 252
5537775 | 3320.001.01 Brannslokking Sprinkler våt 252
5537885 | 3320.001.01 Brannslokking Sprinkler våt 252
5537944 | 3320.001.01 Brannslokking Sprinkler våt 252
5538064 | 3320.001.01 Brannslokking Sprinkler våt 253
5538630 | 3320.001.01 Brannslokking Sprinkler våt 167
5538928 | 3320.001.01 Brannslokking Sprinkler våt 167
5539476 | 3320.001.01 Brannslokking Sprinkler våt 167
5539619 | 3320.001.01 Brannslokking Sprinkler våt 167
5539963 | 3320.001.01 Brannslokking Sprinkler våt 255
5540024 | 3320.001.01 Brannslokking Sprinkler våt 255
5540153 | 3320.001.01 Brannslokking Sprinkler våt 255
5540163 | 3320.001.01 Brannslokking Sprinkler våt 255
5540332 | 3320.001.01 Brannslokking Sprinkler våt 255
5540491 | 3320.001.01 Brannslokking Sprinkler våt 255
5540498 | 3320.001.01 Brannslokking Sprinkler våt 255
5540532 | 3320.001.01 Brannslokking Sprinkler våt 255
5540642 | 3320.001.01 Brannslokking Sprinkler våt 255
5541257 | 3320.001.01 Brannslokking Sprinkler våt 255
5541263 | 3320.001.01 Brannslokking Sprinkler våt 255
5541351 | 3320.001.01 Brannslokking Sprinkler våt 257
5543287 | 3320.001.01 Brannslokking Sprinkler våt 258
5543601 | 3320.001.01 Brannslokking Sprinkler våt 258
5544262 | 3320.001.01 Brannslokking Sprinkler våt 258
5545629 | 3320.001.01 Brannslokking Sprinkler våt 260

# IfcFlowFitting: RS_53_PIF_UN_Tee-Reduced-EN10241_MC_gen:RS_53_PIF_UN_Tee-Reduced-EN10241_MC_gen (13)
In: H01-Nivå D+0,36
Type - Material: 3320.001
ePset_Simplebim - Assembly Level: Leaf
ePset_LocationTool - Splitting: ORIGINAL
Name (RS_53_PIF_UN_Tee-Reduced-EN10241_MC_gen:RS_53_PIF_UN_Tee-Reduced-EN10241_MC_gen:...) | Group
5535919 | 3320.001.01 Brannslokking Sprinkler våt 248
5536650 | 3320.001.01 Brannslokking Sprinkler våt 249
5537626 | 3320.001.01 Brannslokking Sprinkler våt 252
5537767 | 3320.001.01 Brannslokking Sprinkler våt 252
5537877 | 3320.001.01 Brannslokking Sprinkler våt 252
5537968 | 3320.001.01 Brannslokking Sprinkler våt 252
5540145 | 3320.001.01 Brannslokking Sprinkler våt 255
5540155 | 3320.001.01 Brannslokking Sprinkler våt 255
5540330 | 3320.001.01 Brannslokking Sprinkler våt 255
5540451 | 3320.001.01 Brannslokking Sprinkler våt 255
5540489 | 3320.001.01 Brannslokking Sprinkler våt 255
5540496 | 3320.001.01 Brannslokking Sprinkler våt 255
5540874 | 3320.001.01 Brannslokking Sprinkler våt 255

# IfcFlowFitting: Sveis:Sveis (14)
In: H01-Nivå D+0,36
Type - Material: <Unnamed>
ePset_Simplebim - Assembly Level: Leaf
Name (Sveis:Sveis:...) | Splitting
5534894 | ORIGINAL
5534896 | ORIGINAL
5534906 | ORIGINAL
5534908 | ORIGINAL
5534920 | ORIGINAL
5534922 | ORIGINAL
5534932 | ORIGINAL
5534934 | ORIGINAL
5541490 | ORIGINAL
5652201 | ORIGINAL
5652203 | ORIGINAL
5652217 | ORIGINAL
5652219 | ORIGINAL
5541492 | RESULT

# IfcFlowFitting: magicirc_elbow_full_radius_NOR:magicirc_elbow_full_radius_NOR (7)
In: H01-Nivå D+0,36
Type - Material: 3601.001 Avtrekk
ePset_Simplebim - Assembly Level: Leaf
Name (magicirc_elbow_full_radius_NOR:magicirc_elbow_full_radius_NOR:...) | Splitting | Group
5483374 | ORIGINAL | 36.03 Avtrekk 1.etg nord og øst + nordfløy: 1
5483520 | ORIGINAL | 36.03 Avtrekk 1.etg nord og øst + nordfløy: 1
5514940 | ORIGINAL | 36.26 Avtrekk Bagasjehall 1.etg: 1
5561178 | ORIGINAL | 36.03 Tilluft 1.etg nord og øst + nordfløy: 1
5561259 | ORIGINAL | 36.03 Tilluft 1.etg nord og øst + nordfløy: 1
5561336 | ORIGINAL | 36.03 Avtrekk 1.etg nord og øst + nordfløy: 1
5514944 | RESULT | 36.26 Avtrekk Bagasjehall 1.etg: 1

# IfcFlowFitting: magicirc_elbow_full_radius_NOR:magicirc_elbow_full_radius_NOR (6)
In: H01-Nivå D+0,36
Type - Material: 3601.001 Tilluft
ePset_Simplebim - Assembly Level: Leaf
Name (magicirc_elbow_full_radius_NOR:magicirc_elbow_full_radius_NOR:...) | Splitting | Group
5472597 | ORIGINAL | 36.03 Tilluft 1.etg nord og øst + nordfløy: 1
5472605 | ORIGINAL | 36.03 Tilluft 1.etg nord og øst + nordfløy: 1
5561382 | ORIGINAL | 36.03 Avtrekk 1.etg nord og øst + nordfløy: 1
5561551 | ORIGINAL | 36.03 Tilluft 1.etg nord og øst + nordfløy: 1
5561506 | RESULT | 36.03 Tilluft 1.etg nord og øst + nordfløy: 1
5508737 | RESULT | 36.26 Tilluft Bagasjehall 1.etg: 1

# IfcFlowFitting: magicirc_reduction_NOR:magicirc_reduction_NOR, magicirc_reduction_NOR:magicirc_reduction_NOR:5483528
In: H01-Nivå D+0,36
Type - Material: Material_Duct
ePset_Simplebim - Assembly Level: Leaf
ePset_LocationTool - Splitting: ORIGINAL
Group: 36.03 Avtrekk 1.etg nord og øst + nordfløy: 1

# IfcFlowFitting: magicirc_tapoutlet_001:magicirc_tapoutlet_001 (2)
In: H01-Nivå D+0,36
Type - Material: 3601.001 Avtrekk
ePset_Simplebim - Assembly Level: Leaf
ePset_LocationTool - Splitting: ORIGINAL
Group: 36.03 Avtrekk 1.etg nord og øst + nordfløy: 1
Name (magicirc_tapoutlet_001:magicirc_tapoutlet_001:...)
5561340
5561386

# IfcFlowFitting: magicirc_tapoutlet_001:magicirc_tapoutlet_001 (3)
In: H01-Nivå D+0,36
Type - Material: 3601.001 Tilluft
ePset_Simplebim - Assembly Level: Leaf
ePset_LocationTool - Splitting: ORIGINAL
Group: 36.03 Tilluft 1.etg nord og øst + nordfløy: 1
Name (magicirc_tapoutlet_001:magicirc_tapoutlet_001:...)
5561182
5561251
5561555

# IfcFlowSegment: Cable Tray with Fittings:Kabelstige (5)
In: H01-Nivå D+0,36
Type - PredefinedType: CABLETRAYSEGMENT; Material: Kabelstige
ePset_SimplebimBasicQuantities - Height (Simplebim): 25 mm
ePset_Simplebim - Assembly Level: Leaf
ePset_LocationTool - Splitting: RESULT
Name (Cable Tray with Fittings:Kabelstige:...) | Width (Simplebim) (mm) | Length (Simplebim) (mm)
2735710 | 400 | 5288
2733792 | 600 | 10823
2745517 | 600 | 10823
2796172 | 600 | 10723
2796506 | 400 | 925

# IfcFlowSegment: Pipe Types:Pressfittingssystem MM (14)
In: H01-Nivå D+0,36
Type - Material: 3200.003 Tur
ePset_Simplebim - Assembly Level: Leaf
Name (Pipe Types:Pressfittingssystem MM:...) | Width (Simplebim) (mm) | Height (Simplebim) (mm) | Length (Simplebim) (mm) | Splitting | Group
5632344 | 15 | 15 | 436.92 | ORIGINAL | 3200.00x.xx Varme Radiator Tur 55° 2
5632393 | 15 | 15 | 436.92 | ORIGINAL | 3200.00x.xx Varme Radiator Retur 40° 2
5632520 | 15 | 15 | 149.295 | ORIGINAL | 3200.00x.xx Varme Radiator Retur 40° 2
5632524 | 15 | 15 | 149.295 | ORIGINAL | 3200.00x.xx Varme Radiator Tur 55° 2
5639856 | 15 | 15 | 92 | ORIGINAL | 3200.00x.xx Varme Radiator Retur 40° 7
5639760 | 15 | 16 | 4614 | RESULT | 3200.00x.xx Varme Radiator Tur 55° 7
5639846 | 15 | 16 | 4615 | RESULT | 3200.00x.xx Varme Radiator Retur 40° 7
5639868 | 15 | 16 | 4765 | RESULT | 3200.00x.xx Varme Radiator Retur 40° 7
5636206 | 54 | 54 | 1366 | RESULT | 3200.00x.xx Varme Retur 35° 1
5637669 | 54 | 54 | 1006 | RESULT | 3200.00x.xx Varme Tur 55° 1
5636192 | 54 | 54 | 1749 | RESULT | 3200.00x.xx Varme Retur 35° 1
5637663 | 54 | 54 | 1249 | RESULT | 3200.00x.xx Varme Tur 55° 1
5650556 | 54 | 54 | 1748 | RESULT | 3200.00x.xx Varme Retur 35° 1
5650575 | 54 | 54 | 1248 | RESULT | 3200.00x.xx Varme Tur 55° 1

# IfcFlowSegment: Pipe Types:Stålrør sveist og gjenget (70)
In: H01-Nivå D+0,36
Type - Material: 3320.001
ePset_Simplebim - Assembly Level: Leaf
Name (Pipe Types:Stålrør sveist og gjenget:...) | Splitting | Length (Simplebim) (mm) | Height (Simplebim) (mm) | Width (Simplebim) (mm) | Group
5534884 | ORIGINAL | 4650 | 114.3 | 114.3 | 3320.001.01 Brannslokking Sprinkler våt 2
5534898 | ORIGINAL | 3130 | 114.3 | 114.3 | 3320.001.01 Brannslokking Sprinkler våt 2
5534910 | ORIGINAL | 4720.63 | 114.3 | 114.3 | 3320.001.01 Brannslokking Sprinkler våt 2
5534924 | ORIGINAL | 1626.45 | 114.3 | 114.3 | 3320.001.01 Brannslokking Sprinkler våt 2
5535678 | ORIGINAL | 41.8031 | 33.7 | 33.7 | 3320.001.01 Brannslokking Sprinkler våt 248
5535710 | ORIGINAL | 361.25 | 33.7 | 33.7 | 3320.001.01 Brannslokking Sprinkler våt 248
5535714 | ORIGINAL | 237.767 | 33.7 | 33.7 | 3320.001.01 Brannslokking Sprinkler våt 248
5535944 | ORIGINAL | 3153.28 | 33.7 | 33.7 | 3320.001.01 Brannslokking Sprinkler våt 248
5536021 | ORIGINAL | 206.705 | 42.4 | 42.4 | 3320.001.01 Brannslokking Sprinkler våt 249
5536283 | ORIGINAL | 89.1119 | 42.4 | 42.4 | 3320.001.01 Brannslokking Sprinkler våt 249
5536558 | ORIGINAL | 301.71 | 33.7 | 33.7 | 3320.001.01 Brannslokking Sprinkler våt 249
5536573 | ORIGINAL | 827.531 | 33.7186 | 33.7 | 3320.001.01 Brannslokking Sprinkler våt 249
5536651 | ORIGINAL | 2055.1 | 42.4 | 42.4 | 3320.001.01 Brannslokking Sprinkler våt 249
5536816 | ORIGINAL | 436.731 | 33.7 | 33.7 | 3320.001.01 Brannslokking Sprinkler våt 249
5536856 | ORIGINAL | 63.2696 | 33.7 | 33.7 | 3320.001.01 Brannslokking Sprinkler våt 249
5537033 | ORIGINAL | 636.733 | 33.7 | 33.7 | 3320.001.01 Brannslokking Sprinkler våt 253
5537306 | ORIGINAL | 36.7333 | 33.7 | 33.7 | 3320.001.01 Brannslokking Sprinkler våt 252
5537357 | ORIGINAL | 327.93 | 42.4 | 42.4 | 3320.001.01 Brannslokking Sprinkler våt 252
5537497 | ORIGINAL | 703.308 | 33.743 | 33.7 | 3320.001.01 Brannslokking Sprinkler våt 252
5537627 | ORIGINAL | 2986.5 | 42.4427 | 42.4 | 3320.001.01 Brannslokking Sprinkler våt 252
5537661 | ORIGINAL | 404.957 | 33.7001 | 33.7 | 3320.001.01 Brannslokking Sprinkler våt 252
5537768 | ORIGINAL | 759.721 | 42.4 | 42.4 | 3320.001.01 Brannslokking Sprinkler våt 252
5537796 | ORIGINAL | 404.957 | 33.7001 | 33.7 | 3320.001.01 Brannslokking Sprinkler våt 252
5537835 | ORIGINAL | 1179.85 | 33.7 | 33.7 | 3320.001.01 Brannslokking Sprinkler våt 252
5537878 | ORIGINAL | 759.721 | 42.4 | 42.4 | 3320.001.01 Brannslokking Sprinkler våt 252
5537900 | ORIGINAL | 703.308 | 33.7462 | 33.7 | 3320.001.01 Brannslokking Sprinkler våt 252
5537913 | ORIGINAL | 161.25 | 33.7 | 33.7 | 3320.001.01 Brannslokking Sprinkler våt 252
5537918 | ORIGINAL | 523.609 | 33.7491 | 33.7 | 3320.001.01 Brannslokking Sprinkler våt 252
5537969 | ORIGINAL | 2149.88 | 42.4 | 42.4 | 3320.001.01 Brannslokking Sprinkler våt 252
5538062 | ORIGINAL | 236.733 | 33.7 | 33.7 | 3320.001.01 Brannslokking Sprinkler våt 253
5538622 | ORIGINAL | 604.907 | 33.7002 | 33.7 | 3320.001.01 Brannslokking Sprinkler våt 167
5538926 | ORIGINAL | 636.733 | 33.7 | 33.7 | 3320.001.01 Brannslokking Sprinkler våt 167
5539472 | ORIGINAL | 604.907 | 33.7002 | 33.7 | 3320.001.01 Brannslokking Sprinkler våt 167
5539615 | ORIGINAL | 604.907 | 33.7002 | 33.7 | 3320.001.01 Brannslokking Sprinkler våt 167
5539961 | ORIGINAL | 50.0475 | 33.7 | 33.7 | 3320.001.01 Brannslokking Sprinkler våt 255
5540057 | ORIGINAL | 39.9 | 33.7 | 33.7 | 3320.001.01 Brannslokking Sprinkler våt 255
5540071 | ORIGINAL | 39.9 | 33.7 | 33.7 | 3320.001.01 Brannslokking Sprinkler våt 255
5540146 | ORIGINAL | 1705.8 | 42.4 | 42.4 | 3320.001.01 Brannslokking Sprinkler våt 255
5540156 | ORIGINAL | 1527.34 | 42.4 | 42.4 | 3320.001.01 Brannslokking Sprinkler våt 255
5540327 | ORIGINAL | 39.9 | 33.7 | 33.7 | 3320.001.01 Brannslokking Sprinkler våt 255
5540409 | ORIGINAL | 469.8 | 42.4 | 42.4 | 3320.001.01 Brannslokking Sprinkler våt 255
5540421 | ORIGINAL | 347.021 | 42.4 | 42.4 | 3320.001.01 Brannslokking Sprinkler våt 255
5540431 | ORIGINAL | 750.4 | 42.4 | 42.4 | 3320.001.01 Brannslokking Sprinkler våt 255
5540486 | ORIGINAL | 39.9 | 33.7 | 33.7 | 3320.001.01 Brannslokking Sprinkler våt 255
5540493 | ORIGINAL | 39.9 | 33.7 | 33.7 | 3320.001.01 Brannslokking Sprinkler våt 255
5540500 | ORIGINAL | 469.8 | 42.4 | 42.4 | 3320.001.01 Brannslokking Sprinkler våt 255
5540527 | ORIGINAL | 50.0475 | 33.7 | 33.7 | 3320.001.01 Brannslokking Sprinkler våt 255
5540577 | ORIGINAL | 935.182 | 42.4 | 42.4 | 3320.001.01 Brannslokking Sprinkler våt 255
5540587 | ORIGINAL | 347.021 | 42.4 | 42.4 | 3320.001.01 Brannslokking Sprinkler våt 255
5540601 | ORIGINAL | 1481.34 | 33.7 | 33.7 | 3320.001.01 Brannslokking Sprinkler våt 255
5540703 | ORIGINAL | 542.839 | 33.7 | 33.7 | 3320.001.01 Brannslokking Sprinkler våt 255
5540740 | ORIGINAL | 262.45 | 42.4 | 42.4 | 3320.001.01 Brannslokking Sprinkler våt 255
5540742 | ORIGINAL | 1429.28 | 42.4 | 42.4 | 3320.001.01 Brannslokking Sprinkler våt 255
5540746 | ORIGINAL | 975.22 | 33.7 | 33.7 | 3320.001.01 Brannslokking Sprinkler våt 255
5540875 | ORIGINAL | 2477.19 | 42.4 | 42.4 | 3320.001.01 Brannslokking Sprinkler våt 255
5541227 | ORIGINAL | 256.262 | 33.7 | 33.7 | 3320.001.01 Brannslokking Sprinkler våt 255
5541307 | ORIGINAL | 612.912 | 33.7 | 33.7 | 3320.001.01 Brannslokking Sprinkler våt 257
5541437 | ORIGINAL | 5623.13 | 76.1 | 76.1 | 3320.001.01 Brannslokking Sprinkler våt 2
5543283 | ORIGINAL | 604.907 | 33.7008 | 33.7 | 3320.001.01 Brannslokking Sprinkler våt 258
5543806 | ORIGINAL | 588.545 | 33.7 | 33.7 | 3320.001.01 Brannslokking Sprinkler våt 258
5544258 | ORIGINAL | 604.907 | 33.7008 | 33.7 | 3320.001.01 Brannslokking Sprinkler våt 258
5545608 | ORIGINAL | 615.057 | 33.7 | 33.7 | 3320.001.01 Brannslokking Sprinkler våt 260
5534872 | RESULT | 939 | 114 | 114 | 3320.001.01 Brannslokking Sprinkler våt 2
5535920 | RESULT | 908 | 42 | 42 | 3320.001.01 Brannslokking Sprinkler våt 248
5633232 | RESULT | 2338 | 76 | 76 | 3700.001.05 Kjøle Retur 18° 2
5633576 | RESULT | 2738 | 76 | 76 | 3700.001.04 Kjøle Tur 14° 1
5643647 | RESULT | 2428 | 76 | 76 | 3700.001.05 Kjøle Retur 18° 3
5643694 | RESULT | 2948 | 76 | 76 | 3700.001.04 Kjøle Tur 10° 2
5650485 | RESULT | 2428 | 76 | 76 | 3700.001.05 Kjøle Retur 18° 3
5650513 | RESULT | 2948 | 76 | 76 | 3700.001.04 Kjøle Tur 10° 2

# IfcFlowSegment: Round Duct:Sirkulær kanal (68)
Type - Material: 3601.001 Tilluft
ePset_Simplebim - Assembly Level: Leaf
Name (Round Duct:Sirkulær kanal:...) | In | Height (Simplebim) (mm) | Width (Simplebim) (mm) | Length (Simplebim) (mm) | Splitting | Group
5469861 | H01-Nivå D+0,36 | 160.026 | 160 | 807.327 | ORIGINAL | 36.03 Tilluft 1.etg nord og øst + nordfløy: 1
5469879 | H01-Nivå D+0,36 | 160.002 | 160 | 569.401 | ORIGINAL | 36.03 Tilluft 1.etg nord og øst + nordfløy: 1
5469979 | H01-Nivå D+0,36 | 160 | 100.006 | 160.003 | ORIGINAL | 36.03 Tilluft 1.etg nord og øst + nordfløy: 1
5470043 | H01-Nivå D+0,36 | 160.095 | 160 | 2847.26 | ORIGINAL | 36.03 Tilluft 1.etg nord og øst + nordfløy: 1
5470045 | H01-Nivå D+0,36 | 160.004 | 160 | 569.401 | ORIGINAL | 36.03 Tilluft 1.etg nord og øst + nordfløy: 1
5470051 | H01-Nivå D+0,36 | 160 | 150.004 | 160.003 | ORIGINAL | 36.03 Tilluft 1.etg nord og øst + nordfløy: 1
5470421 | H01-Nivå D+0,36 | 315 | 315 | 615.545 | ORIGINAL | 36.03 Tilluft 1.etg nord og øst + nordfløy: 1
5470425 | H01-Nivå D+0,36 | 160 | 160 | 492.365 | ORIGINAL | 36.03 Tilluft 1.etg nord og øst + nordfløy: 1
5472319 | H01-Nivå D+0,36 | 315 | 315 | 80.4342 | ORIGINAL | 36.03 Tilluft 1.etg nord og øst + nordfløy: 1
5472321 | H01-Nivå D+0,36 | 200 | 200 | 452.4 | ORIGINAL | 36.03 Tilluft 1.etg nord og øst + nordfløy: 1
5472329 | H01-Nivå D+0,36 | 160 | 160 | 492.365 | ORIGINAL | 36.03 Tilluft 1.etg nord og øst + nordfløy: 1
5472337 | H01-Nivå D+0,36 | 160 | 160 | 492.365 | ORIGINAL | 36.03 Tilluft 1.etg nord og øst + nordfløy: 1
5472345 | H01-Nivå D+0,36 | 315 | 315 | 3119 | ORIGINAL | 36.03 Tilluft 1.etg nord og øst + nordfløy: 1
5472347 | H01-Nivå D+0,36 | 315 | 315 | 2644 | ORIGINAL | 36.03 Tilluft 1.etg nord og øst + nordfløy: 1
5472493 | H01-Nivå D+0,36 | 315 | 315 | 758.701 | ORIGINAL | 36.03 Tilluft 1.etg nord og øst + nordfløy: 1
5472589 | H01-Nivå D+0,36 | 250 | 250 | 227.516 | ORIGINAL | 36.03 Tilluft 1.etg nord og øst + nordfløy: 1
5472591 | H01-Nivå D+0,36 | 104.4 | 250 | 250 | ORIGINAL | 36.03 Tilluft 1.etg nord og øst + nordfløy: 1
5472595 | H01-Nivå D+0,36 | 250 | 250 | 30 | ORIGINAL | 36.03 Tilluft 1.etg nord og øst + nordfløy: 1
5472599 | H01-Nivå D+0,36 | 104.4 | 250 | 250 | ORIGINAL | 36.03 Tilluft 1.etg nord og øst + nordfløy: 1
5472603 | H01-Nivå D+0,36 | 250 | 250 | 33.2097 | ORIGINAL | 36.03 Tilluft 1.etg nord og øst + nordfløy: 1
5472607 | H01-Nivå D+0,36 | 250 | 250 | 5762.49 | ORIGINAL | 36.03 Tilluft 1.etg nord og øst + nordfløy: 1
5473220 | H01-Nivå D+0,36 | 315 | 315 | 645 | ORIGINAL | 36.03 Tilluft 1.etg nord og øst + nordfløy: 1
5480794 | H01-Nivå D+0,36 | 250 | 250 | 2144 | ORIGINAL | 36.03 Avtrekk 1.etg nord og øst + nordfløy: 1
5481045 | H01-Nivå D+0,36 | 250 | 250 | 1844 | ORIGINAL | 36.03 Avtrekk 1.etg nord og øst + nordfløy: 1
5481057 | H01-Nivå D+0,36 | 250 | 250 | 150 | ORIGINAL | 36.03 Avtrekk 1.etg nord og øst + nordfløy: 1
5481109 | H01-Nivå D+0,36 | 250 | 250 | 696.167 | ORIGINAL | 36.03 Avtrekk 1.etg nord og øst + nordfløy: 1
5481745 | H01-Nivå D+0,36 | 315 | 315 | 16.9074 | ORIGINAL | 36.03 Avtrekk 1.etg nord og øst + nordfløy: 1
5481859 | H01-Nivå D+0,36 | 315 | 315 | 1404 | ORIGINAL | 36.03 Avtrekk 1.etg nord og øst + nordfløy: 1
5481865 | H01-Nivå D+0,36 | 315 | 315 | 2144 | ORIGINAL | 36.03 Avtrekk 1.etg nord og øst + nordfløy: 1
5482143 | H01-Nivå D+0,36 | 315 | 315 | 824 | ORIGINAL | 36.03 Avtrekk 1.etg nord og øst + nordfløy: 1
5482153 | H01-Nivå D+0,36 | 315 | 315 | 1789 | ORIGINAL | 36.03 Avtrekk 1.etg nord og øst + nordfløy: 1
5482163 | H01-Nivå D+0,36 | 315 | 315 | 2229 | ORIGINAL | 36.03 Avtrekk 1.etg nord og øst + nordfløy: 1
5482188 | H01-Nivå D+0,36 | 315 | 315 | 150 | ORIGINAL | 36.03 Avtrekk 1.etg nord og øst + nordfløy: 1
5483225 | H01-Nivå D+0,36 | 72.2949 | 250 | 250 | ORIGINAL | 36.03 Avtrekk 1.etg nord og øst + nordfløy: 1
5483274 | H01-Nivå D+0,36 | 250 | 250 | 5017 | ORIGINAL | 36.03 Avtrekk 1.etg nord og øst + nordfløy: 1
5483364 | H01-Nivå D+0,36 | 250 | 250 | 453.785 | ORIGINAL | 36.03 Avtrekk 1.etg nord og øst + nordfløy: 1
5483484 | H01-Nivå D+0,36 | 250 | 250 | 453.785 | ORIGINAL | 36.03 Avtrekk 1.etg nord og øst + nordfløy: 1
5483518 | H01-Nivå D+0,36 | 104.4 | 250 | 250 | ORIGINAL | 36.03 Avtrekk 1.etg nord og øst + nordfløy: 1
5483574 | H01-Nivå D+0,36 | 250 | 250 | 176.661 | ORIGINAL | 36.03 Avtrekk 1.etg nord og øst + nordfløy: 1
5508643 | H01-Nivå D+0,36 | 456.623 | 250 | 540.893 | ORIGINAL | 36.26 Tilluft Bagasjehall 1.etg: 1
5514725 | H01-Nivå D+0,36 | 607.739 | 315 | 607.739 | ORIGINAL | 36.26 Avtrekk Bagasjehall 1.etg: 1
5561175 | H01-Nivå D+0,36 | 547.996 | 315 | 547.996 | ORIGINAL | 36.03 Tilluft 1.etg nord og øst + nordfløy: 1
5561247 | H01-Nivå D+0,36 | 547.996 | 315 | 547.996 | ORIGINAL | 36.03 Tilluft 1.etg nord og øst + nordfløy: 1
5561333 | H01-Nivå D+0,36 | 447.891 | 315 | 447.891 | ORIGINAL | 36.03 Avtrekk 1.etg nord og øst + nordfløy: 1
5561379 | H01-Nivå D+0,36 | 420.968 | 250 | 420.968 | ORIGINAL | 36.03 Avtrekk 1.etg nord og øst + nordfløy: 1
5561548 | H01-Nivå D+0,36 | 483.733 | 160 | 483.75 | ORIGINAL | 36.03 Tilluft 1.etg nord og øst + nordfløy: 1
5524874 | H02-Nivå F-3,5 m | 630 | 630 | 4515 | RESULT | 3601.001.05 Avtrekk: 9
5524733 | H02-Nivå F-3,5 m | 630 | 630 | 2727 | RESULT | 3601.001.04 Tilluft: 10
5508499 | H01-Nivå D+0,36 | 316 | 315 | 3578 | RESULT | 36.26 Tilluft Bagasjehall 1.etg: 1
5514701 | H01-Nivå D+0,36 | 316 | 315 | 2073 | RESULT | 36.26 Avtrekk Bagasjehall 1.etg: 1
5509381 | H01-Nivå D+0,36 | 316 | 315 | 2500 | RESULT | 36.26 Tilluft Bagasjehall 1.etg: 1
5469097 | H01-Nivå D+0,36 | 324 | 628 | 7163 | RESULT | 36.03 Tilluft 1.etg nord og øst + nordfløy: 1
5480885 | H01-Nivå D+0,36 | 160 | 160 | 514 | RESULT | 36.03 Avtrekk 1.etg nord og øst + nordfløy: 1
5480971 | H01-Nivå D+0,36 | 160 | 160 | 514 | RESULT | 36.03 Avtrekk 1.etg nord og øst + nordfløy: 1
5482063 | H01-Nivå D+0,36 | 160 | 160 | 482 | RESULT | 36.03 Avtrekk 1.etg nord og øst + nordfløy: 1
5482077 | H01-Nivå D+0,36 | 160 | 160 | 482 | RESULT | 36.03 Avtrekk 1.etg nord og øst + nordfløy: 1
5483148 | H01-Nivå D+0,36 | 315 | 315 | 2742 | RESULT | 36.03 Avtrekk 1.etg nord og øst + nordfløy: 1
5480987 | H01-Nivå D+0,36 | 160 | 160 | 514 | RESULT | 36.03 Avtrekk 1.etg nord og øst + nordfløy: 1
5481861 | H01-Nivå D+0,36 | 160 | 160 | 482 | RESULT | 36.03 Avtrekk 1.etg nord og øst + nordfløy: 1
5482021 | H01-Nivå D+0,36 | 160 | 160 | 482 | RESULT | 36.03 Avtrekk 1.etg nord og øst + nordfløy: 1
5482035 | H01-Nivå D+0,36 | 160 | 160 | 482 | RESULT | 36.03 Avtrekk 1.etg nord og øst + nordfløy: 1
5482049 | H01-Nivå D+0,36 | 160 | 160 | 482 | RESULT | 36.03 Avtrekk 1.etg nord og øst + nordfløy: 1
5489201 | H01-Nivå D+0,36 | 425 | 630 | 4567 | RESULT | 36.03 Avtrekk 1.etg nord og øst + nordfløy: 1
5472609 | H01-Nivå D+0,36 | 250 | 250 | 1955 | RESULT | 36.03 Tilluft 1.etg nord og øst + nordfløy: 1
5470457 | H01-Nivå D+0,36 | 315 | 315 | 527 | RESULT | 36.03 Tilluft 1.etg nord og øst + nordfløy: 1
5481409 | H01-Nivå D+0,36 | 315 | 315 | 361 | RESULT | 36.03 Avtrekk 1.etg nord og øst + nordfløy: 1
5481541 | H01-Nivå D+0,36 | 160 | 160 | 482 | RESULT | 36.03 Avtrekk 1.etg nord og øst + nordfløy: 1
5509075 | H01-Nivå D+0,36 | 316 | 315 | 490 | RESULT | 36.26 Tilluft Bagasjehall 1.etg: 1

# IfcFlowTerminal: C80 surfaced:C80-S1150 BL G2 3600 830 (9)
In: H01-Nivå D+0,36
Type - Material: <Unnamed>, Glamox Light Source
Classification: UP003 (Uniformat)
ePset_Simplebim - Assembly Level: Leaf
Name (C80 surfaced:C80-S1150 BL G2 3600 830:...) | Splitting
2885101 | ORIGINAL
2885102 | ORIGINAL
2885124 | ORIGINAL
2885128 | ORIGINAL
2885129 | ORIGINAL
2885138 | ORIGINAL
2885143 | ORIGINAL
2885222 | ORIGINAL
2885152 | RESULT

# IfcFlowTerminal: SSP K80 HIMLING:SP-15-K80-68DGR-RS (7)
In: H01-Nivå D+0,36
Type - Material: 3320.001
ePset_Simplebim - Assembly Level: Leaf
ePset_LocationTool - Splitting: ORIGINAL
Group: 3320.001.01 Brannslokking Sprinkler våt 255
Name (SSP K80 HIMLING:SP-15-K80-68DGR-RS:...)
5539965
5540061
5540075
5540329
5540488
5540495
5540529

# IfcFlowTerminal: SU-15-K80-68DGR-STD:SU-15-K80-68DGR-STD (17)
In: H01-Nivå D+0,36
Type - Material: 3320.001
ePset_Simplebim - Assembly Level: Leaf
ePset_LocationTool - Splitting: ORIGINAL
Name (SU-15-K80-68DGR-STD:SU-15-K80-68DGR-STD:...) | Group
5536731 | 3320.001.01 Brannslokking Sprinkler våt 249
5536855 | 3320.001.01 Brannslokking Sprinkler våt 249
5537030 | 3320.001.01 Brannslokking Sprinkler våt 253
5537305 | 3320.001.01 Brannslokking Sprinkler våt 252
5537660 | 3320.001.01 Brannslokking Sprinkler våt 252
5537795 | 3320.001.01 Brannslokking Sprinkler våt 252
5538061 | 3320.001.01 Brannslokking Sprinkler våt 253
5538621 | 3320.001.01 Brannslokking Sprinkler våt 167
5538925 | 3320.001.01 Brannslokking Sprinkler våt 167
5539471 | 3320.001.01 Brannslokking Sprinkler våt 167
5539614 | 3320.001.01 Brannslokking Sprinkler våt 167
5540665 | 3320.001.01 Brannslokking Sprinkler våt 255
5541154 | 3320.001.01 Brannslokking Sprinkler våt 257
5543282 | 3320.001.01 Brannslokking Sprinkler våt 258
5543596 | 3320.001.01 Brannslokking Sprinkler våt 258
5544257 | 3320.001.01 Brannslokking Sprinkler våt 258
5545533 | 3320.001.01 Brannslokking Sprinkler våt 260

# IfcFlowTerminal: UD2002 Spredenett - 2 uttak - Påvegg_Vegg:UD2002, UD2002 Spredenett - 2 uttak - Påvegg_Vegg:UD2002:2985146
In: H01-Nivå D+0,36
Type - Material: Plastic - White
Classification: UD002 (Uniformat)
ePset_LocationTool - Splitting: ORIGINAL
ePset_Simplebim - Assembly Level: Leaf

# IfcMember: Rectangular Mullion:80 x 40 mm (6)
In: H02-Nivå F-3,5 m
Type - PredefinedType: MULLION; Material: Metal - Aluminium
Pset_MemberCommon - Reference: Rectangular Mullion:80 x 40 mm
ePset_SimplebimBasicQuantities - Width (Simplebim): 40 mm
ePset_Simplebim - Assembly Level: Leaf
ePset_LocationTool - Splitting: ORIGINAL
Name (Rectangular Mullion:80 x 40 mm:...) | Volume, net (Simplebim) (m3) | Height (Simplebim) (mm) | Length (Simplebim) (mm) | Weight, as steel (Simplebim) (kg) | Area, sides, net (Simplebim) (m2)
12531015 | 0.002048 | 640 | 80 | 16.0768 | 0.16
12531016 | 0.0074832 | 80 | 2338.5 | 58.7431 | 0.56764
12531017 | 0.007168 | 2240 | 80 | 56.2688 | 0.544
12531019 | 0.0069712 | 80 | 2178.5 | 54.7239 | 0.52924
12531020 | 0.002048 | 640 | 80 | 16.0768 | 0.16
12531021 | 0.007168 | 2240 | 80 | 56.2688 | 0.544

# IfcPlate: System Panel:A234 - Systemglass, System Panel:A234 - Systemglass:12530935
In: H02-Nivå F-3,5 m
Type - PredefinedType: CURTAIN_PANEL; Material: _Flesland Glass
ePset_Simplebim - Assembly Level: Leaf
ePset_SimplebimBasicQuantities - Area, largest surface, net (Simplebim): 1.3071 m2; Volume, net (Simplebim): 0.0326775 m3; Weight, as steel (Simplebim): 256.518 kg
ePset_LocationTool - Splitting: ORIGINAL
Pset_PlateCommon - Reference: System Panel:A234 - Systemglass

# IfcSlab: Floor:Eikeparkett 22mm (2)
In: H02-Nivå F-3,5 m
Type - PredefinedType: FLOOR; Material: Tre 22 mm
Pset_SlabCommon - Reference: Floor:Eikeparkett 22mm
ePset_LocationTool - Splitting: RESULT
ePset_Simplebim - Assembly Level: Leaf
ePset_SimplebimBasicQuantities - Thickness (Simplebim): 22 mm
Name (Floor:Eikeparkett 22mm:...) | Volume, net (Simplebim) (m3) | Area, largest surface, net (Simplebim) (m2) | Perimeter (Simplebim) (mm) | Area, top, net (Simplebim) (m2) | Area, sides, net (Simplebim) (m2)
13940027 | 0.0658967 | 2.99533 | 8208.78 | 2.99529 | 0.180593
13930801 | 0.762246 | 34.6479 | 27789.4 | 34.6473 | 0.611366

# IfcSlab: Floor:Generic 138mm, Floor:Generic 138mm:9242385
In: H02-Nivå F-3,5 m
Type - PredefinedType: FLOOR; Material: <Unnamed> 138 mm
Pset_SlabCommon - Reference: Floor:Generic 138mm
ePset_Simplebim - Assembly Level: Leaf
ePset_SimplebimBasicQuantities - Volume, net (Simplebim): 32.7021 m3; Area, largest surface, net (Simplebim): 236.972 m2; Perimeter (Simplebim): 66274 mm; Thickness (Simplebim): 138 mm; Area, sides, net (Simplebim): 9.14581 m2; Area, top, net (Simplebim): 236.972 m2
ePset_LocationTool - Splitting: RESULT

# IfcSlab: Floor:Generic 650mm, Floor:Generic 650mm:745878
In: H03-Nivå G-4,3m
Type - PredefinedType: FLOOR; Material: _NSW Betong 650 mm
ePset_SimplebimBasicQuantities - Volume, net (Simplebim): 82.9402 m3; Area, top, net (Simplebim): 236.972 m2; Area, largest surface, net (Simplebim): 236.972 m2; Thickness (Simplebim): 350 mm; Perimeter (Simplebim): 66274.4 mm; Area, sides, net (Simplebim): 23.196 m2
Pset_SlabCommon - Reference: Floor:Generic 650mm
ePset_Simplebim - Assembly Level: Leaf
ePset_LocationTool - Splitting: RESULT

# IfcWall: Basic Wall:A242 - Standard 100, Basic Wall:A242 - Standard 100:12078003
In: H03-Nivå G-5m
Type - PredefinedType: STANDARD; Material: _NSW Standard 100 mm
ePset_SimplebimBasicQuantities - Volume, net (Simplebim): 0.0907638 m3; Area, largest surface, net (Simplebim): 0.927639 m2; Area, side, net, larger (Simplebim): 0.927639 m2; Area, side, gross, larger (Simplebim): 0.927639 m2; Area, side, net, average (Simplebim): 0.907639 m2; Area, side, gross, average (Simplebim): 0.907639 m2; Area, side, gross, smaller (Simplebim): 0.887638 m2; Area, side, net, smaller (Simplebim): 0.887638 m2; Area, side, gross, AABB (Simplebim): 0.9276 m2; Thickness (Simplebim): 100 mm; Height (Simplebim): 400 mm; Length (Simplebim): 2319 mm
ePset_Simplebim - Assembly Level: Leaf
Pset_WallCommon - Reference: Basic Wall:A242 - Standard 100
ePset_LocationTool - Splitting: RESULT

# IfcWall: Basic Wall:A242 - Standard 120 (8)
Type - PredefinedType: STANDARD; Material: _NSW Standard 120 mm
ePset_Simplebim - Assembly Level: Leaf
ePset_SimplebimBasicQuantities - Thickness (Simplebim): 120 mm
Pset_WallCommon - Reference: Basic Wall:A242 - Standard 120
ePset_LocationTool - Splitting: RESULT
Name (Basic Wall:A242 - Standard 120:...) | In | Volume, net (Simplebim) (m3) | Area, side, net, smaller (Simplebim) (m2) = Area, side, gross, smaller (Simplebim) (m2) | Area, side, gross, AABB (Simplebim) (m2) | Area, side, gross, average (Simplebim) (m2) = Area, side, net, average (Simplebim) (m2) | Height (Simplebim) (mm) | Length (Simplebim) (mm) | Area, side, gross, larger (Simplebim) (m2) = Area, side, net, larger (Simplebim) (m2) | Area, largest surface, net (Simplebim) (m2)
12069648 | H03-Nivå G-5m | 0.136371 | 1.11843 | 1.1544 | 1.13643 | 300 | 3848 | 1.15443 | 1.15443
12069699 | H03-Nivå G-5m | 0.131047 | 1.07405 | 1.11 | 1.09205 | 300 | 3700 | 1.11005 | 1.11005
12070039 | H03-Nivå G-5m | 0.139424 | 1.23245 | 1.2684 | 1.2515 | 300 | 4228 | 1.27055 | 1.23245
12704217 | H01-Nivå D+0,36 | 0.100854 | 0.84045 | 0.84045 | 0.84045 | 862 | 975 | 0.84045 | 0.84045
279719 | H01-Nivå D+0,36 | 0.111777 | 0.879754 | 0.983542 | 0.931474 | 862 | 1141 | 0.983194 | 0.983194
155929 | H01-Nivå D+0,36 | 0.950351 | 7.91959 | 7.91919 | 7.91959 | 862 | 9187 | 7.91959 | 7.91959
156288 | H01-Nivå D+0,36 | 0.0288598 | 0.240498 | 0.240498 | 0.240498 | 862 | 279 | 0.240498 | 0.240498
156715 | H01-Nivå D+0,36 | 0.234715 | 1.90424 | 2.00846 | 1.95596 | 862 | 2330 | 2.00768 | 2.00768

# IfcWall: Basic Wall:A242 - Standard 125 (2)
In: H01-Nivå D+0,36
Type - PredefinedType: STANDARD; Material: _NSW Standard 125 mm
Pset_WallCommon - Reference: Basic Wall:A242 - Standard 125
ePset_SimplebimBasicQuantities - Thickness (Simplebim): 126 mm; Height (Simplebim): 862 mm
ePset_Simplebim - Assembly Level: Leaf
ePset_LocationTool - Splitting: RESULT
Name (Basic Wall:A242 - Standard 125:...) | Area, side, net, smaller (Simplebim) (m2) = Area, side, gross, smaller (Simplebim) (m2) | Area, side, net, average (Simplebim) (m2) = Area, side, gross, average (Simplebim) (m2) | Area, side, net, larger (Simplebim) (m2) = Area, largest surface, net (Simplebim) (m2) = Area, side, gross, larger (Simplebim) (m2) | Volume, net (Simplebim) (m3) | Area, side, gross, AABB (Simplebim) (m2) | Length (Simplebim) (mm)
12084028 | 3.30898 | 3.36285 | 3.41673 | 0.420356 | 3.41697 | 3964
155702 | 1.14266 | 1.19654 | 1.25041 | 0.149567 | 1.25076 | 1451

# IfcWall: Basic Wall:A242 - Standard 150, Basic Wall:A242 - Standard 150:157117
In: H01-Nivå D+0,36
Type - PredefinedType: STANDARD; Material: _NSW Standard 150 mm
ePset_LocationTool - Splitting: RESULT
ePset_SimplebimBasicQuantities - Volume, net (Simplebim): 0.495542 m3; Area, side, gross, larger (Simplebim): 3.30362 m2; Area, side, net, smaller (Simplebim): 3.30362 m2; Area, side, gross, smaller (Simplebim): 3.30362 m2; Area, side, net, larger (Simplebim): 3.30362 m2; Area, side, net, average (Simplebim): 3.30362 m2; Area, largest surface, net (Simplebim): 3.30362 m2; Area, side, gross, average (Simplebim): 3.30362 m2; Area, side, gross, AABB (Simplebim): 3.30318 m2; Thickness (Simplebim): 150 mm; Height (Simplebim): 862 mm; Length (Simplebim): 3832 mm
ePset_Simplebim - Assembly Level: Leaf
Pset_WallCommon - Reference: Basic Wall:A242 - Standard 150

# IfcWall: Basic Wall:A242 - Standard 170, Basic Wall:A242 - Standard 170:2027387
In: H03-Nivå G-5m
Type - PredefinedType: STANDARD; Material: _NSW Standard 170 mm
ePset_Simplebim - Assembly Level: Leaf
ePset_LocationTool - Splitting: RESULT
ePset_SimplebimBasicQuantities - Area, side, gross, larger (Simplebim): 0.2144 m2; Area, side, net, average (Simplebim): 0.2144 m2; Area, largest surface, net (Simplebim): 0.2144 m2; Area, side, net, smaller (Simplebim): 0.2144 m2; Area, side, gross, smaller (Simplebim): 0.2144 m2; Area, side, net, larger (Simplebim): 0.2144 m2; Area, side, gross, AABB (Simplebim): 0.2144 m2; Area, side, gross, average (Simplebim): 0.2144 m2; Volume, net (Simplebim): 0.036448 m3; Thickness (Simplebim): 170 mm; Height (Simplebim): 400 mm; Length (Simplebim): 536 mm
Pset_WallCommon - Reference: Basic Wall:A242 - Standard 170

# IfcWall: Basic Wall:A242 - Standard 225, Basic Wall:A242 - Standard 225:865498
In: H02-Nivå F-3,5 m
Type - PredefinedType: STANDARD; Material: _NSW Standard 225 mm
ePset_LocationTool - Splitting: RESULT
ePset_SimplebimBasicQuantities - Area, side, gross, smaller (Simplebim): 4.64622 m2; Area, side, net, smaller (Simplebim): 4.64622 m2; Area, side, gross, AABB (Simplebim): 5.4457 m2; Area, side, gross, average (Simplebim): 5.0456 m2; Area, side, net, average (Simplebim): 5.0456 m2; Area, side, gross, larger (Simplebim): 5.44497 m2; Area, side, net, larger (Simplebim): 5.44497 m2; Area, largest surface, net (Simplebim): 5.44497 m2; Thickness (Simplebim): 226 mm; Length (Simplebim): 1534 mm; Height (Simplebim): 3550 mm; Volume, net (Simplebim): 1.13526 m3
ePset_Simplebim - Assembly Level: Leaf
Pset_WallCommon - Reference: Basic Wall:A242 - Standard 225

# IfcWall: Basic Wall:A242 - Standard 50 (5)
In: H02-Nivå F-3,5 m
Type - PredefinedType: STANDARD; Material: _NSW Standard 50 mm
ePset_LocationTool - Splitting: RESULT
ePset_Simplebim - Assembly Level: Leaf
Pset_WallCommon - Reference: Basic Wall:A242 - Standard 50
ePset_SimplebimBasicQuantities - Thickness (Simplebim): 50 mm; Height (Simplebim): 3900 mm
Name (Basic Wall:A242 - Standard 50:...) | Area, side, gross, AABB (Simplebim) (m2) | Length (Simplebim) (mm) | Area, side, gross, larger (Simplebim) (m2) = Area, largest surface, net (Simplebim) (m2) = Area, side, net, larger (Simplebim) (m2) | Volume, net (Simplebim) (m3) | Area, side, gross, average (Simplebim) (m2) = Area, side, net, average (Simplebim) (m2) | Area, side, gross, smaller (Simplebim) (m2) = Area, side, net, smaller (Simplebim) (m2)
12526369 | 2.6988 | 692 | 2.68607 | 0.129428 | 2.58856 | 2.49104
12526675 | 0.7449 | 191 | 0.745696 | 0.0372848 | 0.745696 | 0.745696
12526694 | 1.755 | 450 | 1.75675 | 0.0876645 | 1.75329 | 1.74983
12526721 | 1.4664 | 376 | 1.45906 | 0.0729529 | 1.45906 | 1.45906
12526738 | 2.8002 | 718 | 2.79169 | 0.139585 | 2.79169 | 2.79169

# IfcWall: Basic Wall:A242 - Standard 70 (3)
In: H01-Nivå D+0,36
Type - PredefinedType: STANDARD; Material: _NSW Standard 70 mm
ePset_Simplebim - Assembly Level: Leaf
Pset_WallCommon - Reference: Basic Wall:A242 - Standard 70
ePset_SimplebimBasicQuantities - Thickness (Simplebim): 70 mm; Height (Simplebim): 700 mm
ePset_LocationTool - Splitting: RESULT
Name (Basic Wall:A242 - Standard 70:...) | Area, side, gross, AABB (Simplebim) (m2) | Area, side, gross, average (Simplebim) (m2) = Area, side, net, smaller (Simplebim) (m2) = Area, side, gross, smaller (Simplebim) (m2) = Area, side, net, larger (Simplebim) (m2) = Area, side, net, average (Simplebim) (m2) = Area, largest surface, net (Simplebim) (m2) = Area, side, gross, larger (Simplebim) (m2) | Length (Simplebim) (mm) | Volume, net (Simplebim) (m3)
13301566 | 0.3864 | 0.38605 | 552 | 0.0270235
13301583 | 0.3164 | 0.316537 | 452 | 0.0221576
13301603 | 0.3374 | 0.33705 | 482 | 0.0235935

# IfcWall: Basic Wall:Glassvegg (2)
In: H01-Nivå D+0,36
Type - PredefinedType: STANDARD; Material: _Flesland Glass 100 mm
ePset_LocationTool - Splitting: RESULT
Pset_WallCommon - Reference: Basic Wall:Glassvegg
ePset_Simplebim - Assembly Level: Leaf
ePset_SimplebimBasicQuantities - Thickness (Simplebim): 100 mm; Height (Simplebim): 390 mm
Name (Basic Wall:Glassvegg:...) | Volume, net (Simplebim) (m3) | Area, side, gross, AABB (Simplebim) (m2) | Area, side, gross, smaller (Simplebim) (m2) = Area, side, net, smaller (Simplebim) (m2) | Area, side, gross, average (Simplebim) (m2) = Area, side, net, average (Simplebim) (m2) | Length (Simplebim) (mm) | Area, side, gross, larger (Simplebim) (m2) = Area, side, net, larger (Simplebim) (m2) = Area, largest surface, net (Simplebim) (m2)
13290262 | 0.168608 | 1.70547 | 1.66658 | 1.68608 | 4373 | 1.70558
13487376 | 0.05187 | 0.5187 | 0.5187 | 0.5187 | 1330 | 0.5187

# IfcWall: Basic Wall:NSW Innvendig - Glassvegg 50, Basic Wall:NSW Innvendig - Glassvegg 50:6571427
In: H02-Nivå F-3,5 m
Type - PredefinedType: STANDARD; Material: Glass 50 mm
Pset_WallCommon - Reference: Basic Wall:NSW Innvendig - Glassvegg 50
ePset_Simplebim - Assembly Level: Leaf
ePset_SimplebimBasicQuantities - Area, side, gross, average (Simplebim): 4.20957 m2; Area, side, gross, AABB (Simplebim): 2.80805 m2; Area, side, gross, smaller (Simplebim): 4.12082 m2; Area, side, net, smaller (Simplebim): 2.62982 m2; Area, side, net, larger (Simplebim): 2.80732 m2; Area, largest surface, net (Simplebim): 2.80732 m2; Thickness (Simplebim): 50 mm; Length (Simplebim): 791 mm; Height (Simplebim): 3550 mm; Area, side, gross, larger (Simplebim): 4.29832 m2; Area, side, net, average (Simplebim): 2.71857 m2; Volume, net (Simplebim): 0.135929 m3
ePset_LocationTool - Splitting: RESULT

# IfcWall: Basic Wall:NSW Utvendig - Standard 169 GF (2)
In: H01-Nivå D+0,36
Type - PredefinedType: STANDARD; Material: Flesland - Finishes - Exterior - GF 169 mm
ePset_LocationTool - Splitting: RESULT
Pset_WallCommon - Reference: Basic Wall:NSW Utvendig - Standard 169 GF
ePset_Simplebim - Assembly Level: Leaf
ePset_SimplebimBasicQuantities - Thickness (Simplebim): 168 mm; Height (Simplebim): 862 mm
Name (Basic Wall:NSW Utvendig - Standard 169 GF:...) | Area, side, gross, larger (Simplebim) (m2) = Area, side, net, larger (Simplebim) (m2) = Area, largest surface, net (Simplebim) (m2) | Volume, net (Simplebim) (m3) | Area, side, gross, AABB (Simplebim) (m2) | Area, side, net, smaller (Simplebim) (m2) = Area, side, gross, smaller (Simplebim) (m2) | Length (Simplebim) (mm) | Area, side, net, average (Simplebim) (m2) = Area, side, gross, average (Simplebim) (m2)
340309 | 2.5836 | 0.424318 | 2.58341 | 2.43792 | 2997 | 2.51076
6327921 | 1.96514 | 0.319799 | 1.96536 | 1.81946 | 2280 | 1.8923

# IfcWall: Basic Wall:NSW Utvendig - Standard 268 Panels (4)
In: H03-Nivå G-5m
Type - PredefinedType: STANDARD; Material: Flesland - Finishes - Exterior - Metal Panel 268 mm
ePset_LocationTool - Splitting: RESULT
Pset_WallCommon - Reference: Basic Wall:NSW Utvendig - Standard 268 Panels
ePset_Simplebim - Assembly Level: Leaf
ePset_SimplebimBasicQuantities - Thickness (Simplebim): 268 mm; Height (Simplebim): 400 mm
Name (Basic Wall:NSW Utvendig - Standard 268 Panels:...) | Area, side, gross, larger (Simplebim) (m2) = Area, largest surface, net (Simplebim) (m2) = Area, side, net, larger (Simplebim) (m2) | Area, side, gross, AABB (Simplebim) (m2) | Area, side, gross, smaller (Simplebim) (m2) = Area, side, net, smaller (Simplebim) (m2) | Length (Simplebim) (mm) | Volume, net (Simplebim) (m3) | Area, side, net, average (Simplebim) (m2) = Area, side, gross, average (Simplebim) (m2)
745891 | 0.715238 | 0.7152 | 0.608038 | 1788 | 0.177319 | 0.661638
745892 | 3.21687 | 3.2168 | 3.10967 | 8042 | 0.847757 | 3.16327
745893 | 3.10967 | 3.1096 | 3.00247 | 7774 | 0.819027 | 3.05607
4393195 | 0.684518 | 0.6844 | 0.577318 | 1711 | 0.169086 | 0.630918

# IfcWall: Basic Wall:NSW Utvendig - Standard 380 GF (5)
In: H01-Nivå D+0,36
Type - PredefinedType: STANDARD; Material: Flesland - Finishes - Exterior - GF 380 mm
ePset_SimplebimBasicQuantities - Thickness (Simplebim): 380 mm; Height (Simplebim): 862 mm
ePset_Simplebim - Assembly Level: Leaf
ePset_LocationTool - Splitting: RESULT
Pset_WallCommon - Reference: Basic Wall:NSW Utvendig - Standard 380 GF
Name (Basic Wall:NSW Utvendig - Standard 380 GF:...) | Volume, net (Simplebim) (m3) | Area, side, net, average (Simplebim) (m2) = Area, side, gross, average (Simplebim) (m2) | Area, largest surface, net (Simplebim) (m2) = Area, side, net, larger (Simplebim) (m2) = Area, side, gross, larger (Simplebim) (m2) | Area, side, gross, smaller (Simplebim) (m2) = Area, side, net, smaller (Simplebim) (m2) | Area, side, gross, AABB (Simplebim) (m2) | Length (Simplebim) (mm)
339005 | 1.71314 | 4.50826 | 4.50826 | 4.50826 | 4.50826 | 5230
339624 | 0.615333 | 1.6193 | 1.6193 | 1.6193 | 1.6197 | 1879
339253 | 2.72652 | 7.17506 | 7.33884 | 7.01128 | 7.33907 | 8514
13228618 | 0.505688 | 1.33076 | 1.33076 | 1.33076 | 1.33093 | 1544
13228650 | 0.989231 | 2.60324 | 2.60324 | 2.60324 | 2.60324 | 3020

# IfcWall: Basic Wall:Ny IV R'w48 EI60 dB (3)
In: H01-Nivå D+0,36
Type - PredefinedType: STANDARD; Material: _NSW Standard 120 mm
ePset_SimplebimBasicQuantities - Thickness (Simplebim): 120 mm
Pset_WallCommon - Reference: Basic Wall:Ny IV R'w48 EI60 dB
ePset_Simplebim - Assembly Level: Leaf
ePset_LocationTool - Splitting: RESULT
Name (Basic Wall:Ny IV R'w48 EI60 dB:...) | Area, side, gross, average (Simplebim) (m2) = Area, side, net, average (Simplebim) (m2) | Area, side, gross, AABB (Simplebim) (m2) | Volume, net (Simplebim) (m3) | Area, side, net, smaller (Simplebim) (m2) = Area, side, gross, smaller (Simplebim) (m2) | Height (Simplebim) (mm) | Length (Simplebim) (mm) | Area, side, gross, larger (Simplebim) (m2) = Area, side, net, larger (Simplebim) (m2) = Area, largest surface, net (Simplebim) (m2)
13291943 | 2.48709 | 2.53432 | 0.29845 | 2.43969 | 790 | 3208 | 2.53449
13292123 | 1.8935 | 1.8935 | 0.22722 | 1.8935 | 700 | 2705 | 1.8935
13291997 | 0.381998 | 0.4242 | 0.0458398 | 0.339998 | 700 | 606 | 0.423998

# IfcWall: Basic Wall:Ny IV75 ensidig (2)
In: H01-Nivå D+0,36
Type - PredefinedType: STANDARD; Material: _NSW Standard 75 mm
ePset_SimplebimBasicQuantities - Thickness (Simplebim): 76 mm; Height (Simplebim): 790 mm
Pset_WallCommon - Reference: Basic Wall:Ny IV75 ensidig
ePset_LocationTool - Splitting: RESULT
ePset_Simplebim - Assembly Level: Leaf
Name (Basic Wall:Ny IV75 ensidig:...) | Volume, net (Simplebim) (m3) | Length (Simplebim) (mm) | Area, side, net, smaller (Simplebim) (m2) = Area, side, gross, smaller (Simplebim) (m2) | Area, side, net, larger (Simplebim) (m2) = Area, largest surface, net (Simplebim) (m2) = Area, side, gross, larger (Simplebim) (m2) | Area, side, net, average (Simplebim) (m2) = Area, side, gross, average (Simplebim) (m2) | Area, side, gross, AABB (Simplebim) (m2)
14010401 | 0.21804 | 3680 | 2.9072 | 2.9072 | 2.9072 | 2.9072
14010339 | 0.0381103 | 681 | 0.478512 | 0.537762 | 0.508137 | 0.53799

# IfcWall: Basic Wall:Ny IV75 ensidig lydforbedrende tiltak (2)
In: H01-Nivå D+0,36
Type - PredefinedType: STANDARD; Material: _NSW Standard 75 mm
Pset_WallCommon - Reference: Basic Wall:Ny IV75 ensidig lydforbedrende tiltak
ePset_SimplebimBasicQuantities - Thickness (Simplebim): 76 mm; Height (Simplebim): 790 mm
ePset_Simplebim - Assembly Level: Leaf
ePset_LocationTool - Splitting: RESULT
Name (Basic Wall:Ny IV75 ensidig lydforbedrende tiltak:...) | Area, side, gross, average (Simplebim) (m2) = Area, side, net, average (Simplebim) (m2) | Area, side, net, smaller (Simplebim) (m2) = Area, side, gross, smaller (Simplebim) (m2) | Area, largest surface, net (Simplebim) (m2) = Area, side, net, larger (Simplebim) (m2) = Area, side, gross, larger (Simplebim) (m2) | Area, side, gross, AABB (Simplebim) (m2) | Length (Simplebim) (mm) | Volume, net (Simplebim) (m3)
13965663 | 0.930696 | 0.901071 | 0.960321 | 0.96064 | 1216 | 0.0698022
13965439 | 1.71556 | 1.68594 | 1.74519 | 1.74511 | 2209 | 0.128667

# IfcWallStandardCase: Basic Wall:A242 - Standard 100 (19)
In: H02-Nivå F-3,5 m
Type - PredefinedType: STANDARD; Material: _NSW Standard 100 mm
ePset_LocationTool - Splitting: ORIGINAL
ePset_Simplebim - Assembly Level: Leaf
Pset_WallCommon - Reference: Basic Wall:A242 - Standard 100
ePset_SimplebimBasicQuantities - Height (Simplebim): 3550 mm
Name (Basic Wall:A242 - Standard 100:...) | Area, side, net, smaller (Simplebim) (m2) | Area, side, gross, larger (Simplebim) (m2) | Area, side, gross, AABB (Simplebim) (m2) | Volume, net (Simplebim) (m3) | Area, side, gross, smaller (Simplebim) (m2) | Area, side, gross, average (Simplebim) (m2) | Area, side, net, average (Simplebim) (m2) | Thickness (Simplebim) (mm) | Area, side, net, larger (Simplebim) (m2) | Area, largest surface, net (Simplebim) (m2) | Length (Simplebim) (mm)
11667417 | 22.2429 | 24.7189 | 24.7189 | 2.24204 | 24.3639 | 24.5414 | 22.4204 | 100 | 22.5979 | 22.5979 | 6963.08
11667419 | 6.17204 | 8.34028 | 8.41395 | 0.640566 | 7.87304 | 8.10666 | 6.40566 | 100 | 6.63928 | 6.63928 | 2370.13
11667420 | 2.47379 | 2.82879 | 2.82879 | 0.265129 | 2.47379 | 2.65129 | 2.65129 | 100 | 2.82879 | 2.82879 | 796.843
11667421 | 22.6195 | 22.6932 | 22.6932 | 2.26564 | 22.6195 | 22.6564 | 22.6564 | 100 | 22.6932 | 22.6932 | 6392.45
11668114 | 13.5645 | 15.7372 | 15.7372 | 1.35904 | 15.6855 | 15.7114 | 13.5904 | 100 | 13.6162 | 13.6162 | 4433.01
11668115 | 3.26854 | 3.50582 | 3.50582 | 0.338718 | 3.26854 | 3.38718 | 3.38718 | 100 | 3.50582 | 3.50582 | 987.556
11668116 | 4.15626 | 4.15626 | 4.16131 | 0.415626 | 4.15626 | 4.15626 | 4.15626 | 100 | 4.15626 | 4.15626 | 1172.2
11668118 | 2.2977 | 2.30817 | 2.30817 | 0.230294 | 2.2977 | 2.30294 | 2.30294 | 100 | 2.30817 | 2.30817 | 650.188
11668244 | 2.47745 | 2.51473 | 2.51473 | 0.249609 | 2.47745 | 2.49609 | 2.49609 | 100 | 2.51473 | 2.51473 | 708.374
12515206 | 4.98097 | 5.02278 | 5.02784 | 0.500188 | 4.98097 | 5.00188 | 5.00188 | 100 | 5.02278 | 5.02278 | 1416.29
12515373 | 3.95829 | 3.9709 | 3.9709 | 0.39646 | 3.95829 | 3.96459 | 3.96459 | 100 | 3.9709 | 3.9709 | 1118.56
12515389 | 1.35572 | 1.36833 | 1.36833 | 0.136203 | 1.35572 | 1.36203 | 1.36203 | 100 | 1.36833 | 1.36833 | 385.446
12515414 | 2.28013 | 2.28013 | 2.28013 | 0.228013 | 2.28013 | 2.28013 | 2.28013 | 100 | 2.28013 | 2.28013 | 642.289
12515437 | 0.707954 | 0.712761 | 0.712761 | 0.0710358 | 0.707954 | 0.710358 | 0.710358 | 100 | 0.712761 | 0.712761 | 200.778
12515882 | 0.262086 | 0.262086 | 0.355 | 0.0262086 | 0.262086 | 0.262086 | 0.262086 | 73.827 | 0.262086 | 0.355 | 100
12523960 | 1.01053 | 1.24276 | 1.24276 | 0.112665 | 1.01053 | 1.12665 | 1.12665 | 100 | 1.24276 | 1.24276 | 350.074
12523961 | 1.36688 | 1.36688 | 1.36688 | 0.136688 | 1.36688 | 1.36688 | 1.36688 | 100 | 1.36688 | 1.36688 | 385.037
12523962 | 12.9733 | 12.9733 | 12.9733 | 1.29733 | 12.9733 | 12.9733 | 12.9733 | 100 | 12.9733 | 12.9733 | 3654.46
12526474 | 0.923946 | 0.926639 | 0.950754 | 0.0925293 | 0.923946 | 0.925293 | 0.925293 | 100 | 0.926639 | 0.926639 | 267.818

# IfcWallStandardCase: Basic Wall:A242 - Standard 120, Basic Wall:A242 - Standard 120:12070071
In: H03-Nivå G-5m
Type - PredefinedType: STANDARD; Material: _NSW Standard 120 mm
ePset_Simplebim - Assembly Level: Leaf
ePset_SimplebimBasicQuantities - Area, side, gross, AABB (Simplebim): 1.40168 m2; Length (Simplebim): 4672.26 mm; Volume, net (Simplebim): 0.167594 m3; Thickness (Simplebim): 120 mm; Height (Simplebim): 300 mm; Area, side, gross, larger (Simplebim): 1.39662 m2; Area, side, net, larger (Simplebim): 1.39662 m2; Area, largest surface, net (Simplebim): 1.39662 m2; Area, side, net, average (Simplebim): 1.39662 m2; Area, side, gross, average (Simplebim): 1.39662 m2; Area, side, gross, smaller (Simplebim): 1.39662 m2; Area, side, net, smaller (Simplebim): 1.39662 m2
Pset_WallCommon - Reference: Basic Wall:A242 - Standard 120
ePset_LocationTool - Splitting: ORIGINAL

# IfcWallStandardCase: Basic Wall:A242 - Standard 125, Basic Wall:A242 - Standard 125:11667418
In: H02-Nivå F-3,5 m
Type - PredefinedType: STANDARD; Material: _NSW Standard 125 mm
Pset_WallCommon - Reference: Basic Wall:A242 - Standard 125
ePset_Simplebim - Assembly Level: Leaf
ePset_SimplebimBasicQuantities - Length (Simplebim): 1172.84 mm; Thickness (Simplebim): 125 mm; Area, side, net, average (Simplebim): 3.8255 m2; Area, side, gross, average (Simplebim): 3.8255 m2; Area, side, net, smaller (Simplebim): 3.48744 m2; Area, side, gross, smaller (Simplebim): 3.48744 m2; Height (Simplebim): 3550 mm; Area, side, gross, larger (Simplebim): 4.16357 m2; Area, largest surface, net (Simplebim): 4.16357 m2; Area, side, net, larger (Simplebim): 4.16357 m2; Area, side, gross, AABB (Simplebim): 4.16357 m2; Volume, net (Simplebim): 0.478188 m3
ePset_LocationTool - Splitting: ORIGINAL

# IfcWallStandardCase: Basic Wall:A242 - Standard 225, Basic Wall:A242 - Standard 225:865499
In: H02-Nivå F-3,5 m
Type - PredefinedType: STANDARD; Material: _NSW Standard 225 mm
ePset_SimplebimBasicQuantities - Area, side, net, smaller (Simplebim): 4.6221 m2; Area, side, gross, smaller (Simplebim): 4.6221 m2; Area, side, net, larger (Simplebim): 4.6221 m2; Area, side, net, average (Simplebim): 4.6221 m2; Area, largest surface, net (Simplebim): 4.6221 m2; Area, side, gross, larger (Simplebim): 4.6221 m2; Area, side, gross, average (Simplebim): 4.6221 m2; Area, side, gross, AABB (Simplebim): 4.6221 m2; Volume, net (Simplebim): 1.03997 m3; Thickness (Simplebim): 225 mm; Length (Simplebim): 1302 mm; Height (Simplebim): 3550 mm
ePset_LocationTool - Splitting: ORIGINAL
ePset_Simplebim - Assembly Level: Leaf
Pset_WallCommon - Reference: Basic Wall:A242 - Standard 225

# IfcWallStandardCase: Basic Wall:A242 - Standard 50 (2)
In: H02-Nivå F-3,5 m
Type - PredefinedType: STANDARD; Material: _NSW Standard 50 mm
ePset_LocationTool - Splitting: ORIGINAL
ePset_SimplebimBasicQuantities - Thickness (Simplebim): 50 mm; Height (Simplebim): 3550 mm
ePset_Simplebim - Assembly Level: Leaf
Pset_WallCommon - Reference: Basic Wall:A242 - Standard 50
Name (Basic Wall:A242 - Standard 50:...) | Area, side, gross, average (Simplebim) (m2) | Area, side, net, average (Simplebim) (m2) | Area, side, gross, larger (Simplebim) (m2) = Area, side, gross, AABB (Simplebim) (m2) | Area, side, net, larger (Simplebim) (m2) = Area, largest surface, net (Simplebim) (m2) | Area, side, net, smaller (Simplebim) (m2) | Length (Simplebim) (mm) | Volume, net (Simplebim) (m3) | Area, side, gross, smaller (Simplebim) (m2)
1984607 | 7.77518 | 6.09518 | 7.86997 | 6.18997 | 6.00038 | 2216.89 | 0.304759 | 7.68038
1984647 | 10.7093 | 10.7093 | 10.7093 | 10.7093 | 10.7093 | 3016.72 | 0.535467 | 10.7093

# IfcWallStandardCase: Basic Wall:Baffel Lyddemping (10)
In: H01-Nivå D+0,36
Type - PredefinedType: STANDARD; Material: Lyddemping 30 mm
ePset_Simplebim - Assembly Level: Leaf
Pset_WallCommon - Reference: Basic Wall:Baffel Lyddemping
ePset_SimplebimBasicQuantities - Thickness (Simplebim): 30 mm; Height (Simplebim): 600 mm
ePset_LocationTool - Splitting: ORIGINAL
Name (Basic Wall:Baffel Lyddemping:...) | Length (Simplebim) (mm) | Volume, net (Simplebim) (m3) | Area, side, gross, AABB (Simplebim) (m2) = Area, side, gross, average (Simplebim) (m2) = Area, side, gross, larger (Simplebim) (m2) = Area, side, net, average (Simplebim) (m2) = Area, largest surface, net (Simplebim) (m2) = Area, side, net, smaller (Simplebim) (m2) = Area, side, gross, smaller (Simplebim) (m2) = Area, side, net, larger (Simplebim) (m2)
13939573 | 2400 | 0.0432 | 1.44
13939574 | 2400 | 0.0432 | 1.44
13939575 | 2400 | 0.0432 | 1.44
13989919 | 2400 | 0.0432 | 1.44
13989957 | 2400 | 0.0432 | 1.44
13989965 | 2400 | 0.0432 | 1.44
13990018 | 1200 | 0.0216 | 0.72
13990041 | 1200 | 0.0216 | 0.72
13990064 | 2400 | 0.0432 | 1.44
13990147 | 1200 | 0.0216 | 0.72

# IfcWallStandardCase: Basic Wall:NSW Innvendig - Glassvegg 50 (3)
In: H02-Nivå F-3,5 m
Type - PredefinedType: STANDARD; Material: Glass 50 mm
Pset_WallCommon - Reference: Basic Wall:NSW Innvendig - Glassvegg 50
ePset_LocationTool - Splitting: ORIGINAL
ePset_Simplebim - Assembly Level: Leaf
ePset_SimplebimBasicQuantities - Thickness (Simplebim): 50 mm; Height (Simplebim): 3550 mm
Name (Basic Wall:NSW Innvendig - Glassvegg 50:...) | Area, side, gross, AABB (Simplebim) (m2) | Area, side, gross, larger (Simplebim) (m2) = Area, largest surface, net (Simplebim) (m2) = Area, side, net, larger (Simplebim) (m2) | Area, side, net, average (Simplebim) (m2) = Area, side, gross, average (Simplebim) (m2) | Volume, net (Simplebim) (m3) | Area, side, net, smaller (Simplebim) (m2) = Area, side, gross, smaller (Simplebim) (m2) | Length (Simplebim) (mm)
865149 | 5.81754 | 5.81754 | 5.72879 | 0.28644 | 5.64004 | 1638.74
865150 | 6.40734 | 6.37051 | 6.30017 | 0.315009 | 6.22984 | 1804.88
11663887 | 1.62412 | 1.62413 | 1.62413 | 0.0812063 | 1.62413 | 457.5
